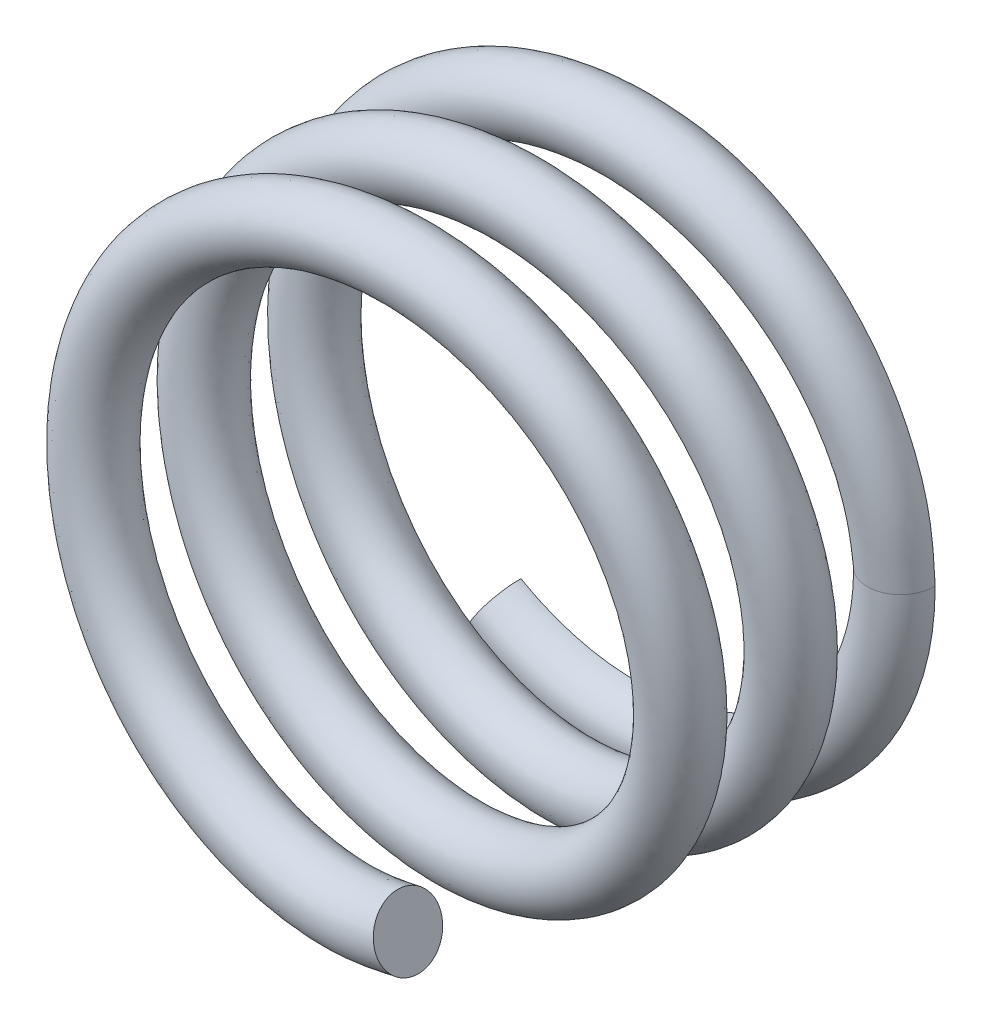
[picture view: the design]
ISO-10303-21;
HEADER;
FILE_DESCRIPTION(('STEP AP214'),'2;1');
FILE_NAME('part.step','',(''),(''),'','','');
FILE_SCHEMA(('AUTOMOTIVE_DESIGN { 1 0 10303 214 1 1 1 1 }'));
ENDSEC;
DATA;
#1=APPLICATION_CONTEXT('core data for automotive mechanical design processes');
#2=APPLICATION_PROTOCOL_DEFINITION('international standard','automotive_design',2000,#1);
#3=PRODUCT_CONTEXT('',#1,'mechanical');
#4=PRODUCT('Part','Part','',(#3));
#5=PRODUCT_RELATED_PRODUCT_CATEGORY('part','',(#4));
#6=PRODUCT_DEFINITION_FORMATION('','',#4);
#7=PRODUCT_DEFINITION_CONTEXT('part definition',#1,'design');
#8=PRODUCT_DEFINITION('design','',#6,#7);
#9=PRODUCT_DEFINITION_SHAPE('','',#8);
#10=(LENGTH_UNIT() NAMED_UNIT(*) SI_UNIT(.MILLI.,.METRE.));
#11=(NAMED_UNIT(*) PLANE_ANGLE_UNIT() SI_UNIT($,.RADIAN.));
#12=(NAMED_UNIT(*) SI_UNIT($,.STERADIAN.) SOLID_ANGLE_UNIT());
#13=UNCERTAINTY_MEASURE_WITH_UNIT(LENGTH_MEASURE(1.E-05),#10,'distance_accuracy_value','');
#14=(GEOMETRIC_REPRESENTATION_CONTEXT(3) GLOBAL_UNCERTAINTY_ASSIGNED_CONTEXT((#13)) GLOBAL_UNIT_ASSIGNED_CONTEXT((#10,
#11,#12)) REPRESENTATION_CONTEXT('',''));
#15=CARTESIAN_POINT('',(0.,0.,0.));
#16=DIRECTION('',(0.,0.,1.));
#17=DIRECTION('',(1.,0.,0.));
#18=AXIS2_PLACEMENT_3D('',#15,#16,#17);
#19=CARTESIAN_POINT('',(12.,0.,1.5));
#20=CARTESIAN_POINT('',(11.9603713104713,0.731177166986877,1.54849427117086));
#21=CARTESIAN_POINT('',(11.8809443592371,2.19666022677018,1.64569032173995));
#22=CARTESIAN_POINT('',(11.2620280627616,4.32325216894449,1.79155371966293));
#23=CARTESIAN_POINT('',(10.2896280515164,6.30509649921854,1.93755795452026));
#24=CARTESIAN_POINT('',(8.96763299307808,8.07535029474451,2.08335110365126));
#25=CARTESIAN_POINT('',(7.34519233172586,9.57242636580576,2.22917046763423));
#26=CARTESIAN_POINT('',(5.47846168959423,10.7517410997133,2.37496569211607));
#27=CARTESIAN_POINT('',(3.42708930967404,11.5698049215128,2.52086018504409));
#28=CARTESIAN_POINT('',(1.26135363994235,12.0005154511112,2.66665382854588));
#29=CARTESIAN_POINT('',(-0.946832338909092,12.0300652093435,2.81251271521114));
#30=CARTESIAN_POINT('',(-3.12287162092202,11.654859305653,2.95832053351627));
#31=CARTESIAN_POINT('',(-5.19533038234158,10.8922151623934,3.10417314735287));
#32=CARTESIAN_POINT('',(-7.09200037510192,9.76130690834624,3.25000059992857));
#33=CARTESIAN_POINT('',(-8.75386804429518,8.30714801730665,3.39582788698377));
#34=CARTESIAN_POINT('',(-10.119061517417,6.57134770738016,3.54167658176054));
#35=CARTESIAN_POINT('',(-11.1493056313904,4.61825453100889,3.68748521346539));
#36=CARTESIAN_POINT('',(-11.8021776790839,2.50856434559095,3.8333513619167));
#37=CARTESIAN_POINT('',(-12.0633531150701,0.315962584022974,3.97914646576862));
#38=CARTESIAN_POINT('',(-11.9177644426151,-1.88765780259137,4.12502086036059));
#39=CARTESIAN_POINT('',(-11.3747674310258,-4.02794086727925,4.27081308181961));
#40=CARTESIAN_POINT('',(-10.4502596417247,-6.03352237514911,4.41668500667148));
#41=CARTESIAN_POINT('',(-9.17529768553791,-7.83637417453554,4.56248507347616));
#42=CARTESIAN_POINT('',(-7.59434030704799,-9.37827116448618,4.70834416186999));
#43=CARTESIAN_POINT('',(-5.75731397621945,-10.6036082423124,4.85416105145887));
#44=CARTESIAN_POINT('',(-3.72922558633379,-11.4773479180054,5.00000024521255));
#45=CARTESIAN_POINT('',(-1.57485201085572,-11.9623402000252,5.14583849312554));
#46=CARTESIAN_POINT('',(0.631550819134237,-12.0515300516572,5.29165624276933));
#47=CARTESIAN_POINT('',(2.81672677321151,-11.7322774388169,5.43751456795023));
#48=CARTESIAN_POINT('',(4.90833399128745,-11.0244622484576,5.58331520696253));
#49=CARTESIAN_POINT('',(6.83434805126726,-9.94391600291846,5.72918674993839));
#50=CARTESIAN_POINT('',(8.53274353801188,-8.53284811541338,5.87497907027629));
#51=CARTESIAN_POINT('',(9.94446517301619,-6.83456494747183,6.02085362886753));
#52=CARTESIAN_POINT('',(11.02333168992,-4.90797393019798,6.16664846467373));
#53=CARTESIAN_POINT('',(11.7338559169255,-2.81700710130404,6.31251511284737));
#54=CARTESIAN_POINT('',(12.0494652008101,-0.631524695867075,6.45832269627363));
#55=CARTESIAN_POINT('',(11.9645671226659,1.57517466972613,6.60417242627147));
#56=CARTESIAN_POINT('',(11.4751000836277,3.72848434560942,6.74999977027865));
#57=CARTESIAN_POINT('',(10.6056574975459,5.75837192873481,6.89582804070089));
#58=CARTESIAN_POINT('',(9.37668509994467,7.59314053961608,7.04167687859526));
#59=CARTESIAN_POINT('',(7.83754685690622,9.17650104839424,7.18748520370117));
#60=CARTESIAN_POINT('',(6.03286015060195,10.4493495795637,7.33335126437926));
#61=CARTESIAN_POINT('',(4.02827918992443,11.3752927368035,7.47914645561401));
#62=CARTESIAN_POINT('',(1.88752245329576,11.9177855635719,7.62502088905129));
#63=CARTESIAN_POINT('',(-0.31580290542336,12.0627488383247,7.77081308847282));
#64=CARTESIAN_POINT('',(-2.50891296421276,11.8032485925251,7.91668499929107));
#65=CARTESIAN_POINT('',(-4.61751183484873,11.1477994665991,8.06248507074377));
#66=CARTESIAN_POINT('',(-6.5724856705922,10.120691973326,8.20834416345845));
#67=CARTESIAN_POINT('',(-8.30552284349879,8.75222611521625,8.35416105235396));
#68=CARTESIAN_POINT('',(-9.76321245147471,7.09339985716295,8.50000024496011));
#69=CARTESIAN_POINT('',(-10.8902055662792,5.19433968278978,8.64583849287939));
#70=CARTESIAN_POINT('',(-11.6568461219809,3.12348707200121,8.79165624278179));
#71=CARTESIAN_POINT('',(-12.0284753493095,0.946606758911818,8.93751456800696));
#72=CARTESIAN_POINT('',(-12.0016452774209,-1.26135683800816,9.08331520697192));
#73=CARTESIAN_POINT('',(-11.5691558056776,-3.42701221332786,9.22918674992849));
#74=CARTESIAN_POINT('',(-10.7519835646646,-5.47832626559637,9.37497907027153));
#75=CARTESIAN_POINT('',(-9.57306626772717,-7.34575168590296,9.52085362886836));
#76=CARTESIAN_POINT('',(-8.0741574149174,-8.96716408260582,9.66664846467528));
#77=CARTESIAN_POINT('',(-6.30509384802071,-10.2890570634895,9.8125151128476));
#78=CARTESIAN_POINT('',(-4.32410519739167,-11.2645705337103,9.95832269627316));
#79=CARTESIAN_POINT('',(-2.19917443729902,-11.8657352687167,10.1041724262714));
#80=CARTESIAN_POINT('',(-1.60519495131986E-06,-12.065633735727,10.2499997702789));
#81=CARTESIAN_POINT('',(2.19920874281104,-11.8660144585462,10.3958280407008));
#82=CARTESIAN_POINT('',(4.32395074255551,-11.2641669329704,10.5416768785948));
#83=CARTESIAN_POINT('',(6.30543594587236,-10.2896447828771,10.6874852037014));
#84=CARTESIAN_POINT('',(8.07366569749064,-8.96661755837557,10.8333512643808));
#85=CARTESIAN_POINT('',(9.57373955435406,-7.34627994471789,10.9791464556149));
#86=CARTESIAN_POINT('',(10.7512111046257,-5.47793880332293,11.1250208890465));
#87=CARTESIAN_POINT('',(11.5699443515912,-3.427247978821,11.2708130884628));
#88=CARTESIAN_POINT('',(12.000853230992,-1.26128638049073,11.4166849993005));
#89=CARTESIAN_POINT('',(12.0290769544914,0.946655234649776,11.5624850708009));
#90=CARTESIAN_POINT('',(11.6563598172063,3.1233395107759,11.7083441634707));
#91=CARTESIAN_POINT('',(10.8904093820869,5.19443501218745,11.8541610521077));
#92=CARTESIAN_POINT('',(9.76322272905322,7.09338571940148,12.0000002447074));
#93=CARTESIAN_POINT('',(8.30536920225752,8.75206173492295,12.1458384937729));
#94=CARTESIAN_POINT('',(6.57277627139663,10.1211088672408,12.2916562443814));
#95=CARTESIAN_POINT('',(4.61727980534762,11.1472422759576,12.4375145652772));
#96=CARTESIAN_POINT('',(2.50909074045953,11.8040237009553,12.5833151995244));
#97=CARTESIAN_POINT('',(0.315783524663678,12.0619260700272,12.7291867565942));
#98=CARTESIAN_POINT('',(-1.88765223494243,11.9186397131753,12.8749790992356));
#99=CARTESIAN_POINT('',(-4.02798501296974,11.3744889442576,13.0208536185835));
#100=CARTESIAN_POINT('',(-6.03322846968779,10.4499868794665,13.1666483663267));
#101=CARTESIAN_POINT('',(-7.8370936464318,9.1759951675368,13.3125151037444));
#102=CARTESIAN_POINT('',(-9.37701853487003,7.5934104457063,13.458322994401));
#103=CARTESIAN_POINT('',(-10.6053987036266,5.75824916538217,13.6041725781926));
#104=CARTESIAN_POINT('',(-11.4751097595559,3.72848984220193,13.7499989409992));
#105=CARTESIAN_POINT('',(-11.9648654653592,1.57523319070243,13.8958273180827));
#106=CARTESIAN_POINT('',(-12.048998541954,-0.631500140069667,14.041679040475));
#107=CARTESIAN_POINT('',(-11.7344478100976,-2.81713283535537,14.1874876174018));
#108=CARTESIAN_POINT('',(-11.0227502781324,-4.90769840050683,14.3333458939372));
#109=CARTESIAN_POINT('',(-9.94535705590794,-6.83518686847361,14.4791398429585));
#110=CARTESIAN_POINT('',(-8.53194028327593,-8.53214432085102,14.6250343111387));
#111=CARTESIAN_POINT('',(-6.83442993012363,-9.94417796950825,14.7708294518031));
#112=CARTESIAN_POINT('',(-4.90864738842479,-11.0234482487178,14.9166489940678));
#113=CARTESIAN_POINT('',(-2.81706134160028,-11.7353683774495,15.0624416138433));
#114=CARTESIAN_POINT('',(-0.631513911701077,-12.046249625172,15.2084468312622));
#115=CARTESIAN_POINT('',(1.58226116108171,-11.9782283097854,15.3543091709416));
#116=CARTESIAN_POINT('',(3.00051631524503,-11.600770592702,15.4515056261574));
#117=CARTESIAN_POINT('',(3.70812820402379,-11.4124451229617,15.4999999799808));
#118=CARTESIAN_POINT('',(15.,0.,1.5));
#119=CARTESIAN_POINT('',(14.9503984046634,0.915065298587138,1.54856790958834));
#120=CARTESIAN_POINT('',(14.8509829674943,2.74911148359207,1.64591155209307));
#121=CARTESIAN_POINT('',(14.0797344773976,5.39818093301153,1.79125837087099));
#122=CARTESIAN_POINT('',(12.8607492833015,7.88413226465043,1.93881104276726));
#123=CARTESIAN_POINT('',(11.2110255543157,10.0923728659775,2.08281692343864));
#124=CARTESIAN_POINT('',(9.17823055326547,11.9683646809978,2.22996355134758));
#125=CARTESIAN_POINT('',(6.85263971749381,13.4374504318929,2.37428555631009));
#126=CARTESIAN_POINT('',(4.27985179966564,14.4637051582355,2.52213780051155));
#127=CARTESIAN_POINT('',(1.58026878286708,15.0003668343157,2.66618767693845));
#128=CARTESIAN_POINT('',(-1.18706321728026,15.0374503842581,2.81337027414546));
#129=CARTESIAN_POINT('',(-3.90143343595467,14.5693225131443,2.95810576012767));
#130=CARTESIAN_POINT('',(-6.49546636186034,13.6147491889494,3.10473477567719));
#131=CARTESIAN_POINT('',(-8.8651140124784,12.2018001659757,3.25025394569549));
#132=CARTESIAN_POINT('',(-10.9413524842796,10.3849920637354,3.39577947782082));
#133=CARTESIAN_POINT('',(-12.6502472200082,8.21249416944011,3.54235768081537));
#134=CARTESIAN_POINT('',(-13.9352839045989,5.77604070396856,3.68704217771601));
#135=CARTESIAN_POINT('',(-14.7537885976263,3.13210446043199,3.83434581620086));
#136=CARTESIAN_POINT('',(-15.0790925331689,0.399344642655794,3.97852178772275));
#137=CARTESIAN_POINT('',(-14.8967742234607,-2.36396364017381,4.12614386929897));
#138=CARTESIAN_POINT('',(-14.2199435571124,-5.03096821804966,4.27022116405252));
#139=CARTESIAN_POINT('',(-13.0609662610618,-7.54551020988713,4.41773758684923));
#140=CARTESIAN_POINT('',(-11.4712442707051,-9.79319756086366,4.56211613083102));
#141=CARTESIAN_POINT('',(-9.49099316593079,-11.7245607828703,4.70910406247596));
#142=CARTESIAN_POINT('',(-7.19775492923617,-13.2541115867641,4.85417719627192));
#143=CARTESIAN_POINT('',(-4.66155947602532,-14.3467267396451,5.00024532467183));
#144=CARTESIAN_POINT('',(-1.96747160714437,-14.9533078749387,5.14631247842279));
#145=CARTESIAN_POINT('',(0.786829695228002,-15.064544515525,5.29138642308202));
#146=CARTESIAN_POINT('',(3.5239615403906,-14.6649121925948,5.43837365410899));
#147=CARTESIAN_POINT('',(6.13168689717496,-13.7822340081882,5.58275293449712));
#148=CARTESIAN_POINT('',(8.54655182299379,-12.4277533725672,5.73026881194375));
#149=CARTESIAN_POINT('',(10.6628244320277,-10.6692289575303,5.87434564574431));
#150=CARTESIAN_POINT('',(12.4332419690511,-8.53974111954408,6.02196817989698));
#151=CARTESIAN_POINT('',(13.7777293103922,-6.13846325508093,6.16614569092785));
#152=CARTESIAN_POINT('',(14.668281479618,-3.51792692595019,6.31345000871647));
#153=CARTESIAN_POINT('',(15.0618775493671,-0.791639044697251,6.45812812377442));
#154=CARTESIAN_POINT('',(14.9556091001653,1.97039074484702,6.6047017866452));
#155=CARTESIAN_POINT('',(14.3440717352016,4.66065168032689,6.75024483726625));
#156=CARTESIAN_POINT('',(13.2577782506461,7.19669863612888,6.89578881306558));
#157=CARTESIAN_POINT('',(11.7196865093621,9.49330067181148,7.04236158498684));
#158=CARTESIAN_POINT('',(9.79958063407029,11.4683488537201,7.18704044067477));
#159=CARTESIAN_POINT('',(7.53798021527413,13.0638137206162,7.33434417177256));
#160=CARTESIAN_POINT('',(5.03949497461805,14.217664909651,7.47852203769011));
#161=CARTESIAN_POINT('',(2.35509325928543,14.8981788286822,7.62614444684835));
#162=CARTESIAN_POINT('',(-0.390530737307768,15.0786246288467,7.77022116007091));
#163=CARTESIAN_POINT('',(-3.14014609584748,14.7534080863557,7.91773740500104));
#164=CARTESIAN_POINT('',(-5.76907499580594,13.9360660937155,8.06211611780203));
#165=CARTESIAN_POINT('',(-8.21784175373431,12.6495593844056,8.20910411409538));
#166=CARTESIAN_POINT('',(-10.3811805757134,10.9412174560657,8.35417720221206));
#167=CARTESIAN_POINT('',(-12.2040468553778,8.86678890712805,8.50024531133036));
#168=CARTESIAN_POINT('',(-13.6134587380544,6.49200294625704,8.64631247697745));
#169=CARTESIAN_POINT('',(-14.5703769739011,3.90688075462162,8.79138642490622));
#170=CARTESIAN_POINT('',(-15.0361243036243,1.18022050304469,8.93837365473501));
#171=CARTESIAN_POINT('',(-15.0024789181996,-1.5726362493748,9.08275293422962));
#172=CARTESIAN_POINT('',(-14.4605255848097,-4.28786680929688,9.23026881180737));
#173=CARTESIAN_POINT('',(-13.442033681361,-6.84397559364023,9.37434564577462));
#174=CARTESIAN_POINT('',(-11.9638595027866,-9.18579065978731,9.52196817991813));
#175=CARTESIAN_POINT('',(-10.0955779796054,-11.2065097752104,9.66614569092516));
#176=CARTESIAN_POINT('',(-7.87849558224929,-12.8632654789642,9.81345000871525));
#177=CARTESIAN_POINT('',(-5.40726960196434,-14.0800668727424,9.95812812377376));
#178=CARTESIAN_POINT('',(-2.74758441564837,-14.8325137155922,10.1047017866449));
#179=CARTESIAN_POINT('',(-1.87839495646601E-05,-15.0822434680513,10.2502448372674));
#180=CARTESIAN_POINT('',(2.74758834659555,-14.8327985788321,10.3957888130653));
#181=CARTESIAN_POINT('',(5.40708316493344,-14.0796754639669,10.5423615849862));
#182=CARTESIAN_POINT('',(7.87881095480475,-12.8638697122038,10.6870404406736));
#183=CARTESIAN_POINT('',(10.0950611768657,-11.2059856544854,10.8343441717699));
#184=CARTESIAN_POINT('',(11.9645132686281,-9.18634461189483,10.9785220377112));
#185=CARTESIAN_POINT('',(13.441246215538,-6.84361723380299,11.1261444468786));
#186=CARTESIAN_POINT('',(14.461304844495,-4.28813445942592,11.2702211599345));
#187=CARTESIAN_POINT('',(15.0016834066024,-1.57259741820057,11.4177374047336));
#188=CARTESIAN_POINT('',(15.0367286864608,1.18023510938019,11.5621161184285));
#189=CARTESIAN_POINT('',(14.5698986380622,3.90670313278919,11.7091041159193));
#190=CARTESIAN_POINT('',(13.6136773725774,6.49206730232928,11.8541772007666));
#191=CARTESIAN_POINT('',(12.204075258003,8.86674982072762,12.0002452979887));
#192=CARTESIAN_POINT('',(10.3810518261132,10.9410293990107,12.1463124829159));
#193=CARTESIAN_POINT('',(8.2181584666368,12.6499594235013,12.2913864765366));
#194=CARTESIAN_POINT('',(5.7688742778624,13.9354958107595,12.4383736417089));
#195=CARTESIAN_POINT('',(3.14035505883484,14.7541767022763,12.5827527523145));
#196=CARTESIAN_POINT('',(0.390544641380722,15.0778008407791,12.7302688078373));
#197=CARTESIAN_POINT('',(-2.35519079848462,14.8990382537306,12.8743462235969));
#198=CARTESIAN_POINT('',(-5.03917032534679,14.2168717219,13.0219684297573));
#199=CARTESIAN_POINT('',(-7.53831923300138,13.0644681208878,13.1661440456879));
#200=CARTESIAN_POINT('',(-9.79910440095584,11.4678626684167,13.3134482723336));
#201=CARTESIAN_POINT('',(-11.7199994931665,9.49359560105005,13.4581320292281));
#202=CARTESIAN_POINT('',(-13.2575009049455,7.19660851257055,13.6047111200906));
#203=CARTESIAN_POINT('',(-14.3440684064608,4.66069990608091,13.7502357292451));
#204=CARTESIAN_POINT('',(-14.9559093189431,1.97045734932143,13.8957558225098));
#205=CARTESIAN_POINT('',(-15.0614083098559,-0.791628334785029,14.0423839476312));
#206=CARTESIAN_POINT('',(-14.6688839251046,-3.51796234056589,14.187120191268));
#207=CARTESIAN_POINT('',(-13.777241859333,-6.13797895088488,14.3343021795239));
#208=CARTESIAN_POINT('',(-12.4341201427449,-8.54044994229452,14.4783523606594));
#209=CARTESIAN_POINT('',(-10.6615801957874,-10.6689719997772,14.6262045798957));
#210=CARTESIAN_POINT('',(-8.54668992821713,-12.4278679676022,14.7705265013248));
#211=CARTESIAN_POINT('',(-6.13373283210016,-13.7803223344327,14.9176733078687));
#212=CARTESIAN_POINT('',(-3.52432662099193,-14.6685911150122,15.0616786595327));
#213=CARTESIAN_POINT('',(-0.783143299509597,-15.0582172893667,15.2092323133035));
#214=CARTESIAN_POINT('',(1.97460691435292,-14.9736241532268,15.3545780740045));
#215=CARTESIAN_POINT('',(3.74956574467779,-14.5012879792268,15.4519221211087));
#216=CARTESIAN_POINT('',(4.63514826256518,-14.2656246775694,15.5004901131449));
#217=CARTESIAN_POINT('',(15.,0.,-1.5));
#218=CARTESIAN_POINT('',(14.9504707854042,0.915076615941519,-1.45143208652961));
#219=CARTESIAN_POINT('',(14.8512004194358,2.74914548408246,-1.35408843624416));
#220=CARTESIAN_POINT('',(14.0794493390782,5.39812567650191,-1.208741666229));
#221=CARTESIAN_POINT('',(12.8618126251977,7.88477268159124,-1.06118881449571));
#222=CARTESIAN_POINT('',(11.2106417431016,10.0920226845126,-0.917183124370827));
#223=CARTESIAN_POINT('',(9.17870901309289,11.968982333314,-0.770036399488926));
#224=CARTESIAN_POINT('',(6.8523267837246,13.436864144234,-0.625714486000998));
#225=CARTESIAN_POINT('',(4.28019566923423,14.4649222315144,-0.47786206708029));
#226=CARTESIAN_POINT('',(1.58022660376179,14.9999169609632,-0.333812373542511));
#227=CARTESIAN_POINT('',(-1.18714699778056,15.0382952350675,-0.186629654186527));
#228=CARTESIAN_POINT('',(-3.90137248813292,14.569125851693,-0.0418942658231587));
#229=CARTESIAN_POINT('',(-6.49573117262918,13.6152427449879,0.104734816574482));
#230=CARTESIAN_POINT('',(-8.86526154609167,12.2020077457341,0.250253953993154));
#231=CARTESIAN_POINT('',(-10.9413369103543,10.3849453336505,0.395779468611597));
#232=CARTESIAN_POINT('',(-12.6508095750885,8.21286733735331,0.542357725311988));
#233=CARTESIAN_POINT('',(-13.9348930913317,5.77585663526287,0.687042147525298));
#234=CARTESIAN_POINT('',(-14.7547492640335,3.13231244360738,0.83434589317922));
#235=CARTESIAN_POINT('',(-15.0784837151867,0.39931820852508,0.978521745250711));
#236=CARTESIAN_POINT('',(-14.8978694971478,-2.36414274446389,1.12614396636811));
#237=CARTESIAN_POINT('',(-14.2194003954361,-5.0307755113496,1.27022111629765));
#238=CARTESIAN_POINT('',(-13.0618599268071,-7.54604528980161,1.41773768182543));
#239=CARTESIAN_POINT('',(-11.4709771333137,-9.79296075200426,1.5621160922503));
#240=CARTESIAN_POINT('',(-9.49144976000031,-11.7251615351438,1.7091041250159));
#241=CARTESIAN_POINT('',(-7.1977695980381,-13.2541280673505,1.85417718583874));
#242=CARTESIAN_POINT('',(-4.66161192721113,-14.3469688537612,2.00024533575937));
#243=CARTESIAN_POINT('',(-1.96753792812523,-14.9537745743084,2.14631250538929));
#244=CARTESIAN_POINT('',(0.786838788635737,-15.0642823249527,2.29138640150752));
#245=CARTESIAN_POINT('',(3.52415401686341,-14.6657399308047,2.43837371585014));
#246=CARTESIAN_POINT('',(6.13147835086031,-13.7817265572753,2.5827528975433));
#247=CARTESIAN_POINT('',(8.5471577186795,-12.4286343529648,2.73026890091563));
#248=CARTESIAN_POINT('',(10.6623912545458,-10.6687889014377,2.87434559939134));
#249=CARTESIAN_POINT('',(12.4341564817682,-8.54035598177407,3.02196827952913));
#250=CARTESIAN_POINT('',(13.7772812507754,-6.13826856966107,3.16614564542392));
#251=CARTESIAN_POINT('',(14.6691868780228,-3.51812292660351,3.31345009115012));
#252=CARTESIAN_POINT('',(15.0616918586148,-0.79163612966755,3.4581280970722));
#253=CARTESIAN_POINT('',(14.9561285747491,1.97048377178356,3.60470182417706));
#254=CARTESIAN_POINT('',(14.3443071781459,4.66072450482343,3.75024484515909));
#255=CARTESIAN_POINT('',(13.2577366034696,7.19670354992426,3.89578880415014));
#256=CARTESIAN_POINT('',(11.7202178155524,9.49372262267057,4.04236163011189));
#257=CARTESIAN_POINT('',(9.79928390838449,11.4680325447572,4.18704041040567));
#258=CARTESIAN_POINT('',(7.53847417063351,13.0646617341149,4.33434424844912));
#259=CARTESIAN_POINT('',(5.03928173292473,14.2170943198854,4.47852199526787));
#260=CARTESIAN_POINT('',(2.3552614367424,14.8992763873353,4.62614454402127));
#261=CARTESIAN_POINT('',(-0.39051530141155,15.0780484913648,4.7702211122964));
#262=CARTESIAN_POINT('',(-3.14037878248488,14.7544231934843,4.91773749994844));
#263=CARTESIAN_POINT('',(-5.76893232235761,13.9357388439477,5.06211607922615));
#264=CARTESIAN_POINT('',(-8.21827203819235,12.6501793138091,5.20910417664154));
#265=CARTESIAN_POINT('',(-10.381191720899,10.9412365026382,5.35417719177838));
#266=CARTESIAN_POINT('',(-12.2042608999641,8.86691360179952,5.50024532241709));
#267=CARTESIAN_POINT('',(-13.6138821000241,6.49221023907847,5.64631250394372));
#268=CARTESIAN_POINT('',(-14.5701304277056,3.90679108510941,5.79138640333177));
#269=CARTESIAN_POINT('',(-15.0369710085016,1.18029323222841,5.93837371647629));
#270=CARTESIAN_POINT('',(-15.0019318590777,-1.57259472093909,6.08275289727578));
#271=CARTESIAN_POINT('',(-14.4615506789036,-4.28817081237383,6.23026890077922));
#272=CARTESIAN_POINT('',(-13.4414813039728,-6.84369960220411,6.37434559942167));
#273=CARTESIAN_POINT('',(-11.9647268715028,-9.18647041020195,6.52196827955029));
#274=CARTESIAN_POINT('',(-10.0952543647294,-11.2061438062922,6.66614564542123));
#275=CARTESIAN_POINT('',(-7.87896177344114,-12.8640659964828,6.8134500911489));
#276=CARTESIAN_POINT('',(-5.40720944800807,-14.079891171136,6.95812809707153));
#277=CARTESIAN_POINT('',(-2.74765646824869,-14.8330365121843,7.10470182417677));
#278=CARTESIAN_POINT('',(-2.22796085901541E-05,-15.0824898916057,7.25024484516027));
#279=CARTESIAN_POINT('',(2.74760588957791,-14.8327604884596,7.39578880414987));
#280=CARTESIAN_POINT('',(5.40732028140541,-14.0803111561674,7.54236163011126));
#281=CARTESIAN_POINT('',(7.87860182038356,-12.8634897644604,7.68704041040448));
#282=CARTESIAN_POINT('',(10.0957150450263,-11.2067174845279,7.83434424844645));
#283=CARTESIAN_POINT('',(11.9640365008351,-9.18596548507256,7.97852199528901));
#284=CARTESIAN_POINT('',(13.4422380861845,-6.8441163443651,8.12614454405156));
#285=CARTESIAN_POINT('',(14.4607521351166,-4.28797110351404,8.27022111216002));
#286=CARTESIAN_POINT('',(15.002720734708,-1.57268980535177,8.41773749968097));
#287=CARTESIAN_POINT('',(15.0363733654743,1.18020054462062,8.56211607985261));
#288=CARTESIAN_POINT('',(14.5706211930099,3.90692078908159,8.70910417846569));
#289=CARTESIAN_POINT('',(13.6136989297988,6.49207201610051,8.85417719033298));
#290=CARTESIAN_POINT('',(12.2042599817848,8.86691484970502,9.00024530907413));
#291=CARTESIAN_POINT('',(10.3813798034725,10.9413679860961,9.14631250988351));
#292=CARTESIAN_POINT('',(8.21799702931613,12.6497526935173,9.29138645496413));
#293=CARTESIAN_POINT('',(5.76920508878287,13.9362785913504,9.43837370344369));
#294=CARTESIAN_POINT('',(3.14022545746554,14.7536434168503,9.58275271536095));
#295=CARTESIAN_POINT('',(0.390572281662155,15.0788696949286,9.73026889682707));
#296=CARTESIAN_POINT('',(-2.35509906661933,14.8984281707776,9.87434617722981));
#297=CARTESIAN_POINT('',(-5.03954880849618,14.2179069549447,10.0219685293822));
#298=CARTESIAN_POINT('',(-7.53807046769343,13.0640458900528,10.166144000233));
#299=CARTESIAN_POINT('',(-9.79972077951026,11.4685519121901,10.3134483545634));
#300=CARTESIAN_POINT('',(-11.7198536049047,9.49348653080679,10.4581320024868));
#301=CARTESIAN_POINT('',(-13.2579834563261,7.19684387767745,10.6047111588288));
#302=CARTESIAN_POINT('',(-14.3442941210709,4.66077603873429,10.7502357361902));
#303=CARTESIAN_POINT('',(-14.9558467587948,1.97042258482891,10.895755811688));
#304=CARTESIAN_POINT('',(-15.0621063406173,-0.791657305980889,11.0423839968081));
#305=CARTESIAN_POINT('',(-14.6685339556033,-3.51789544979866,11.1871201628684));
#306=CARTESIAN_POINT('',(-13.7781067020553,-6.13835908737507,11.3343022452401));
#307=CARTESIAN_POINT('',(-12.4334755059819,-8.54002541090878,11.478352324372));
#308=CARTESIAN_POINT('',(-10.662389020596,-10.6697999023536,11.626204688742));
#309=CARTESIAN_POINT('',(-8.5465301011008,-12.4276278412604,11.7705264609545));
#310=CARTESIAN_POINT('',(-6.1341474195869,-13.78124598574,11.9176733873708));
#311=CARTESIAN_POINT('',(-3.5241616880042,-14.6678611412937,12.0616786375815));
#312=CARTESIAN_POINT('',(-0.783132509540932,-15.0589976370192,12.2092323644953));
#313=CARTESIAN_POINT('',(1.97463615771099,-14.9738962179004,12.3545780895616));
#314=CARTESIAN_POINT('',(3.74967652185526,-14.5016895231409,12.4519221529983));
#315=CARTESIAN_POINT('',(4.63529971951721,-14.2660908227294,12.5004901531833));
#316=CARTESIAN_POINT('',(12.,0.,-1.5));
#317=CARTESIAN_POINT('',(11.9604436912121,0.731188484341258,-1.45150572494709));
#318=CARTESIAN_POINT('',(11.8811618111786,2.19669422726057,-1.35430966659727));
#319=CARTESIAN_POINT('',(11.2617429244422,4.32319691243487,-1.20844631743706));
#320=CARTESIAN_POINT('',(10.2906913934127,6.30573691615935,-1.06244190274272));
#321=CARTESIAN_POINT('',(8.96724918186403,8.07500011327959,-0.916648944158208));
#322=CARTESIAN_POINT('',(7.34567079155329,9.573044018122,-0.770829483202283));
#323=CARTESIAN_POINT('',(5.47814875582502,10.7511548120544,-0.625034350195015));
#324=CARTESIAN_POINT('',(3.42743317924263,11.5710219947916,-0.479139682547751));
#325=CARTESIAN_POINT('',(1.26131146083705,12.0000655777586,-0.333346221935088));
#326=CARTESIAN_POINT('',(-0.946916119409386,12.0309100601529,-0.187487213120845));
#327=CARTESIAN_POINT('',(-3.12281067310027,11.6546626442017,-0.0416794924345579));
#328=CARTESIAN_POINT('',(-5.19559519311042,10.8927087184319,0.104173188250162));
#329=CARTESIAN_POINT('',(-7.09214790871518,9.7615144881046,0.250000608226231));
#330=CARTESIAN_POINT('',(-8.75385247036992,8.30710128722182,0.395827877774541));
#331=CARTESIAN_POINT('',(-10.1196238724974,6.57172087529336,0.541676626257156));
#332=CARTESIAN_POINT('',(-11.1489148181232,4.6180704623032,0.687485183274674));
#333=CARTESIAN_POINT('',(-11.803138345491,2.50877232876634,0.833351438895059));
#334=CARTESIAN_POINT('',(-12.0627442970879,0.315936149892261,0.979146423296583));
#335=CARTESIAN_POINT('',(-11.9188597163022,-1.88783690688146,1.12502095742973));
#336=CARTESIAN_POINT('',(-11.3742242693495,-4.02774816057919,1.27081303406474));
#337=CARTESIAN_POINT('',(-10.4511533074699,-6.03405745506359,1.41668510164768));
#338=CARTESIAN_POINT('',(-9.17503054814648,-7.83613736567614,1.56248503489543));
#339=CARTESIAN_POINT('',(-7.59479690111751,-9.37887191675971,1.70834422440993));
#340=CARTESIAN_POINT('',(-5.75732864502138,-10.6036247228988,1.85416104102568));
#341=CARTESIAN_POINT('',(-3.7292780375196,-11.4775900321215,2.0000002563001));
#342=CARTESIAN_POINT('',(-1.57491833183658,-11.9628068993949,2.14583852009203));
#343=CARTESIAN_POINT('',(0.631559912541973,-12.051267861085,2.29165622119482));
#344=CARTESIAN_POINT('',(2.81691924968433,-11.7331051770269,2.43751462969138));
#345=CARTESIAN_POINT('',(4.9081254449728,-11.0239547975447,2.5833151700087));
#346=CARTESIAN_POINT('',(6.83495394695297,-9.9447969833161,2.72918683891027));
#347=CARTESIAN_POINT('',(8.53231036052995,-8.53240805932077,2.87497902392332));
#348=CARTESIAN_POINT('',(9.94537968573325,-6.83517980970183,3.02085372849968));
#349=CARTESIAN_POINT('',(11.0228836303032,-4.90777924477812,3.16664841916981));
#350=CARTESIAN_POINT('',(11.7347613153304,-2.81720310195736,3.31251519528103));
#351=CARTESIAN_POINT('',(12.0492795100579,-0.631521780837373,3.45832266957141));
#352=CARTESIAN_POINT('',(11.9650865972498,1.57526769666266,3.60417246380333));
#353=CARTESIAN_POINT('',(11.475335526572,3.72855717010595,3.74999977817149));
#354=CARTESIAN_POINT('',(10.6056158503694,5.75837684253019,3.89582803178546));
#355=CARTESIAN_POINT('',(9.37721640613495,7.59356249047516,4.04167692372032));
#356=CARTESIAN_POINT('',(7.83725013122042,9.17618473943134,4.18748517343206));
#357=CARTESIAN_POINT('',(6.03335410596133,10.4501975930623,4.33335134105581));
#358=CARTESIAN_POINT('',(4.02806594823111,11.374722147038,4.47914641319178));
#359=CARTESIAN_POINT('',(1.88769063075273,11.918883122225,4.62502098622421));
#360=CARTESIAN_POINT('',(-0.315787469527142,12.0621727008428,4.77081304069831));
#361=CARTESIAN_POINT('',(-2.50914565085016,11.8042636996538,4.91668509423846));
#362=CARTESIAN_POINT('',(-4.61736916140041,11.1474722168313,5.0624850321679));
#363=CARTESIAN_POINT('',(-6.57291595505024,10.1213119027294,5.20834422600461));
#364=CARTESIAN_POINT('',(-8.30553398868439,8.75224516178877,5.35416104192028));
#365=CARTESIAN_POINT('',(-9.76342649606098,7.09352455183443,5.50000025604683));
#366=CARTESIAN_POINT('',(-10.8906289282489,5.19454697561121,5.64583851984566));
#367=CARTESIAN_POINT('',(-11.6565995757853,3.123397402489,5.79165622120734));
#368=CARTESIAN_POINT('',(-12.0293220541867,0.946679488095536,5.93751462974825));
#369=CARTESIAN_POINT('',(-12.001098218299,-1.26131530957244,6.08331517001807));
#370=CARTESIAN_POINT('',(-11.5701808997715,-3.42731621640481,6.22918683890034));
#371=CARTESIAN_POINT('',(-10.7514311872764,-5.47805027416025,6.37497902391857));
#372=CARTESIAN_POINT('',(-9.57393363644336,-7.3464314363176,6.52085372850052));
#373=CARTESIAN_POINT('',(-8.07383380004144,-8.9667981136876,6.66664841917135));
#374=CARTESIAN_POINT('',(-6.30556003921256,-10.2898575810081,6.81251519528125));
#375=CARTESIAN_POINT('',(-4.32404504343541,-11.2643948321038,6.95832266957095));
#376=CARTESIAN_POINT('',(-2.19924648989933,-11.8662580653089,7.10417246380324));
#377=CARTESIAN_POINT('',(-5.10085397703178E-06,-12.0658801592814,7.24999977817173));
#378=CARTESIAN_POINT('',(2.1992262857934,-11.8659763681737,7.39582803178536));
#379=CARTESIAN_POINT('',(4.32418785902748,-11.264802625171,7.54167692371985));
#380=CARTESIAN_POINT('',(6.30522681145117,-10.2892648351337,7.68748517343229));
#381=CARTESIAN_POINT('',(8.07431956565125,-8.96734938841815,7.83335134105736));
#382=CARTESIAN_POINT('',(9.57326278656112,-7.34590081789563,7.97914641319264));
#383=CARTESIAN_POINT('',(10.7522029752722,-5.47843791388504,8.12502098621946));
#384=CARTESIAN_POINT('',(11.5693916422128,-3.42708462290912,8.27081304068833));
#385=CARTESIAN_POINT('',(12.0018905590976,-1.26137876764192,8.41668509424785));
#386=CARTESIAN_POINT('',(12.0287216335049,0.94662066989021,8.56248503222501));
#387=CARTESIAN_POINT('',(11.657082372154,3.12355716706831,8.70834422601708));
#388=CARTESIAN_POINT('',(10.8904309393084,5.19443972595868,8.85416104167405));
#389=CARTESIAN_POINT('',(9.76340745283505,7.09355074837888,9.00000025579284));
#390=CARTESIAN_POINT('',(8.30569717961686,8.75240032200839,9.14583852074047));
#391=CARTESIAN_POINT('',(6.57261483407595,10.1209021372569,9.29165622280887));
#392=CARTESIAN_POINT('',(4.6176106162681,11.1480250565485,9.43751462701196));
#393=CARTESIAN_POINT('',(2.50896113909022,11.8034904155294,9.58331516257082));
#394=CARTESIAN_POINT('',(0.315811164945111,12.0629949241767,9.72918684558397));
#395=CARTESIAN_POINT('',(-1.88756050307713,11.9180296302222,9.87497905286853));
#396=CARTESIAN_POINT('',(-4.02836349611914,11.3755241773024,10.0208537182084));
#397=CARTESIAN_POINT('',(-6.03297970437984,10.4495646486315,10.1666483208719));
#398=CARTESIAN_POINT('',(-7.83771002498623,9.17668441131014,10.3125151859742));
#399=CARTESIAN_POINT('',(-9.3768726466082,7.59330137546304,10.4583229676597));
#400=CARTESIAN_POINT('',(-10.6058812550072,5.75848453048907,10.6041726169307));
#401=CARTESIAN_POINT('',(-11.475335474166,3.72856597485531,10.7499989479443));
#402=CARTESIAN_POINT('',(-11.9648029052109,1.57519842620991,10.8958273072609));
#403=CARTESIAN_POINT('',(-12.0496965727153,-0.631529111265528,11.0416790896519));
#404=CARTESIAN_POINT('',(-11.7340978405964,-2.81706594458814,11.1874875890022));
#405=CARTESIAN_POINT('',(-11.0236151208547,-4.90807853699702,11.3333459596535));
#406=CARTESIAN_POINT('',(-9.94471241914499,-6.83476233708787,11.4791398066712));
#407=CARTESIAN_POINT('',(-8.53274910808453,-8.53297222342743,11.625034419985));
#408=CARTESIAN_POINT('',(-6.8342701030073,-9.94393784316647,11.7708294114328));
#409=CARTESIAN_POINT('',(-4.90906197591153,-11.0243719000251,11.9166490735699));
#410=CARTESIAN_POINT('',(-2.81689640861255,-11.734638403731,12.0624415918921));
#411=CARTESIAN_POINT('',(-0.631503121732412,-12.0470299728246,12.208446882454));
#412=CARTESIAN_POINT('',(1.58229040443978,-11.9785003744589,12.3543091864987));
#413=CARTESIAN_POINT('',(3.0006270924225,-11.6011721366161,12.451505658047));
#414=CARTESIAN_POINT('',(3.70827966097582,-11.4129112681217,12.5000000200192));
#415=CARTESIAN_POINT('',(9.,0.,-1.5));
#416=CARTESIAN_POINT('',(8.97041659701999,0.547300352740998,-1.45157936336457));
#417=CARTESIAN_POINT('',(8.91112320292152,1.64424297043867,-1.35453089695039));
#418=CARTESIAN_POINT('',(8.44403650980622,3.24826814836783,-1.20815096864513));
#419=CARTESIAN_POINT('',(7.71957016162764,4.72670115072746,-1.06369499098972));
#420=CARTESIAN_POINT('',(6.72385662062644,6.05797754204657,-0.91611476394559));
#421=CARTESIAN_POINT('',(5.51263257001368,7.17710570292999,-0.771622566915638));
#422=CARTESIAN_POINT('',(4.10397072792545,8.06544547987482,-0.624354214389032));
#423=CARTESIAN_POINT('',(2.57467068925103,8.67712175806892,-0.48041729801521));
#424=CARTESIAN_POINT('',(0.942396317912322,9.00021419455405,-0.332880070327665));
#425=CARTESIAN_POINT('',(-0.706685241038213,9.02352488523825,-0.188344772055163));
#426=CARTESIAN_POINT('',(-2.34424885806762,8.74019943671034,-0.0414647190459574));
#427=CARTESIAN_POINT('',(-3.89545921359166,8.17017469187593,0.103611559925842));
#428=CARTESIAN_POINT('',(-5.3190342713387,7.32102123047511,0.24974726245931));
#429=CARTESIAN_POINT('',(-6.56636803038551,6.22925724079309,0.395876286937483));
#430=CARTESIAN_POINT('',(-7.58843816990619,4.93057441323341,0.540995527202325));
#431=CARTESIAN_POINT('',(-8.36293654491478,3.46028428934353,0.68792821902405));
#432=CARTESIAN_POINT('',(-8.85152742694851,1.8852322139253,0.8323569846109));
#433=CARTESIAN_POINT('',(-9.04700487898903,0.232554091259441,0.979771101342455));
#434=CARTESIAN_POINT('',(-8.93984993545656,-1.41153106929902,1.12389794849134));
#435=CARTESIAN_POINT('',(-8.52904814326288,-3.02472080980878,1.27140495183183));
#436=CARTESIAN_POINT('',(-7.8404466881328,-4.52206962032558,1.41563252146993));
#437=CARTESIAN_POINT('',(-6.87908396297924,-5.87931397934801,1.56285397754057));
#438=CARTESIAN_POINT('',(-5.69814404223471,-7.0325822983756,1.70758432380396));
#439=CARTESIAN_POINT('',(-4.31688769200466,-7.95312137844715,1.85414489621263));
#440=CARTESIAN_POINT('',(-2.79694414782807,-8.6082112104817,1.99975517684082));
#441=CARTESIAN_POINT('',(-1.18229873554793,-8.97183922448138,2.14536453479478));
#442=CARTESIAN_POINT('',(0.476281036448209,-9.03825339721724,2.29192604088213));
#443=CARTESIAN_POINT('',(2.10968448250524,-8.80047042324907,2.43665554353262));
#444=CARTESIAN_POINT('',(3.68477253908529,-8.26618303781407,2.58387744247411));
#445=CARTESIAN_POINT('',(5.12275017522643,-7.4609596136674,2.72810477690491));
#446=CARTESIAN_POINT('',(6.4022294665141,-6.39602721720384,2.8756124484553));
#447=CARTESIAN_POINT('',(7.45660288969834,-5.13000363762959,3.01973917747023));
#448=CARTESIAN_POINT('',(8.26848600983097,-3.67728991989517,3.16715119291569));
#449=CARTESIAN_POINT('',(8.80033575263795,-2.11628327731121,3.31158029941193));
#450=CARTESIAN_POINT('',(9.03686716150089,-0.471407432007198,3.45851724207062));
#451=CARTESIAN_POINT('',(8.9740446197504,1.18005162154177,3.6036431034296));
#452=CARTESIAN_POINT('',(8.60636387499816,2.79638983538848,3.74975471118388));
#453=CARTESIAN_POINT('',(7.95349509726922,4.32005013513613,3.89586725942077));
#454=CARTESIAN_POINT('',(7.03421499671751,5.69340235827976,4.04099221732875));
#455=CARTESIAN_POINT('',(5.87521635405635,6.88433693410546,4.18792993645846));
#456=CARTESIAN_POINT('',(4.52823404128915,7.83573345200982,4.33235843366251));
#457=CARTESIAN_POINT('',(3.01685016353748,8.53234997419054,4.47977083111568));
#458=CARTESIAN_POINT('',(1.42011982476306,8.9384898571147,4.62389742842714));
#459=CARTESIAN_POINT('',(-0.241059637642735,9.04629691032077,4.77140496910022));
#460=CARTESIAN_POINT('',(-1.87791251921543,8.85410420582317,4.91563268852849));
#461=CARTESIAN_POINT('',(-3.46580600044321,8.35920558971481,5.06285398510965));
#462=CARTESIAN_POINT('',(-4.92755987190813,7.59244449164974,5.20758427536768));
#463=CARTESIAN_POINT('',(-6.22987625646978,6.56325382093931,5.35414489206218));
#464=CARTESIAN_POINT('',(-7.32259209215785,5.32013550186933,5.49975518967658));
#465=CARTESIAN_POINT('',(-8.16737575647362,3.89688371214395,5.64536453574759));
#466=CARTESIAN_POINT('',(-8.74306872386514,2.3400037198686,5.79192603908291));
#467=CARTESIAN_POINT('',(-9.02167309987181,0.71306574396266,5.9366555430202));
#468=CARTESIAN_POINT('',(-9.00026457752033,-0.950035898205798,6.08387744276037));
#469=CARTESIAN_POINT('',(-8.67881112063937,-2.56646162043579,6.22810477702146));
#470=CARTESIAN_POINT('',(-8.06138107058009,-4.11240094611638,6.37561244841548));
#471=CARTESIAN_POINT('',(-7.18314040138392,-5.50639246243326,6.51973917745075));
#472=CARTESIAN_POINT('',(-6.05241323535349,-6.72745242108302,6.66715119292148));
#473=CARTESIAN_POINT('',(-4.73215830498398,-7.71564916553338,6.81158029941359));
#474=CARTESIAN_POINT('',(-3.24088063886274,-8.44889849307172,6.95851724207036));
#475=CARTESIAN_POINT('',(-1.65083651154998,-8.8994796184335,7.1036431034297));
#476=CARTESIAN_POINT('',(1.20779006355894E-05,-9.04927042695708,7.2497547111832));
#477=CARTESIAN_POINT('',(1.6508466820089,-8.89919224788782,7.39586725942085));
#478=CARTESIAN_POINT('',(3.24105543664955,-8.4492940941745,7.54099221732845));
#479=CARTESIAN_POINT('',(4.73185180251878,-7.71503990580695,7.68792993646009));
#480=CARTESIAN_POINT('',(6.05292408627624,-6.72798129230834,7.83235843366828));
#481=CARTESIAN_POINT('',(7.18248907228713,-5.5058361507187,7.97977083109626));
#482=CARTESIAN_POINT('',(8.06216786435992,-4.11275948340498,8.12389742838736));
#483=CARTESIAN_POINT('',(8.67803114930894,-2.56619814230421,8.27140496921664));
#484=CARTESIAN_POINT('',(9.00106038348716,-0.950067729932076,8.41563268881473));
#485=CARTESIAN_POINT('',(9.02106990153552,0.713040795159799,8.56285398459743));
#486=CARTESIAN_POINT('',(8.74354355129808,2.34019354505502,8.70758427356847));
#487=CARTESIAN_POINT('',(8.16716294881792,3.89680743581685,8.85414489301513));
#488=CARTESIAN_POINT('',(7.32255492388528,5.32018664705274,8.99975520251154));
#489=CARTESIAN_POINT('',(6.23001455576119,6.56343265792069,9.14536453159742));
#490=CARTESIAN_POINT('',(4.92723263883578,7.59205158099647,9.29192599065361));
#491=CARTESIAN_POINT('',(3.46601614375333,8.35977152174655,9.43665555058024));
#492=CARTESIAN_POINT('',(1.87769682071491,8.85333741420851,9.58387760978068));
#493=CARTESIAN_POINT('',(0.241050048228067,9.0471201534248,9.72810479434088));
#494=CARTESIAN_POINT('',(-1.42002193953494,8.93763108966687,9.87561192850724));
#495=CARTESIAN_POINT('',(-3.01717818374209,8.53314139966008,10.0197389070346));
#496=CARTESIAN_POINT('',(-4.52788894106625,7.83508340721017,10.1671526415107));
#497=CARTESIAN_POINT('',(-5.8756992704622,6.88481691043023,10.311582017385));
#498=CARTESIAN_POINT('',(-7.03389168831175,5.6931162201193,10.4585139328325));
#499=CARTESIAN_POINT('',(-7.95377905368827,4.32012518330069,10.6036340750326));
#500=CARTESIAN_POINT('',(-8.60637682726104,2.79635591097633,10.7497621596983));
#501=CARTESIAN_POINT('',(-8.97375905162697,1.17997426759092,10.8958988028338));
#502=CARTESIAN_POINT('',(-9.03728680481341,-0.471400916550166,11.0409741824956));
#503=CARTESIAN_POINT('',(-8.79966172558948,-2.11623643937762,11.1878550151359));
#504=CARTESIAN_POINT('',(-8.26912353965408,-3.67779798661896,11.3323896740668));
#505=CARTESIAN_POINT('',(-7.45594933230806,-5.12949926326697,11.4799272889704));
#506=CARTESIAN_POINT('',(-6.40310919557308,-6.39614454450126,11.6238641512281));
#507=CARTESIAN_POINT('',(-5.12201010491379,-7.46024784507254,11.7711323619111));
#508=CARTESIAN_POINT('',(-3.68397653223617,-8.26749781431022,11.9156247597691));
#509=CARTESIAN_POINT('',(-2.10963112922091,-8.80141566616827,12.0632045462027));
#510=CARTESIAN_POINT('',(-0.479873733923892,-9.03506230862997,12.2076614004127));
#511=CARTESIAN_POINT('',(1.18994465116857,-8.98310453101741,12.3540402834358));
#512=CARTESIAN_POINT('',(2.25157766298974,-8.70065475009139,12.4510891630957));
#513=CARTESIAN_POINT('',(2.78125960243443,-8.55973171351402,12.4995098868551));
#514=CARTESIAN_POINT('',(9.,0.,1.5));
#515=CARTESIAN_POINT('',(8.97034421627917,0.547289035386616,1.54842063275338));
#516=CARTESIAN_POINT('',(8.91090575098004,1.64420896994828,1.64546909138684));
#517=CARTESIAN_POINT('',(8.44432164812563,3.24832340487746,1.79184906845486));
#518=CARTESIAN_POINT('',(7.71850681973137,4.72606073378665,1.93630486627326));
#519=CARTESIAN_POINT('',(6.72424043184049,6.05832772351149,2.08388528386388));
#520=CARTESIAN_POINT('',(5.51215411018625,7.17648805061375,2.22837738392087));
#521=CARTESIAN_POINT('',(4.10428366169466,8.06603176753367,2.37564582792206));
#522=CARTESIAN_POINT('',(2.57432681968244,8.67590468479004,2.51958256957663));
#523=CARTESIAN_POINT('',(0.942438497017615,9.00066406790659,2.6671199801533));
#524=CARTESIAN_POINT('',(-0.706601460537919,9.02268003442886,2.81165515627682));
#525=CARTESIAN_POINT('',(-2.34430980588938,8.74039609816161,2.95853530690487));
#526=CARTESIAN_POINT('',(-3.89519440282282,8.16968113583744,3.10361151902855));
#527=CARTESIAN_POINT('',(-5.31888673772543,7.32081365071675,3.24974725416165));
#528=CARTESIAN_POINT('',(-6.56638360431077,6.22930397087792,3.39587629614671));
#529=CARTESIAN_POINT('',(-7.58787581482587,4.93020124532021,3.54099548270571));
#530=CARTESIAN_POINT('',(-8.36332735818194,3.46046835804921,3.68792824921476));
#531=CARTESIAN_POINT('',(-8.85056676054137,1.88502423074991,3.83235690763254));
#532=CARTESIAN_POINT('',(-9.0476136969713,0.232580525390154,3.97977114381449));
#533=CARTESIAN_POINT('',(-8.93875466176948,-1.41135196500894,4.1238978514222));
#534=CARTESIAN_POINT('',(-8.52959130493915,-3.02491351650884,4.2714049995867));
#535=CARTESIAN_POINT('',(-7.83955302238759,-4.5215345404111,4.41563242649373));
#536=CARTESIAN_POINT('',(-6.87935110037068,-5.87955078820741,4.5628540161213));
#537=CARTESIAN_POINT('',(-5.69768744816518,-7.03198154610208,4.70758426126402));
#538=CARTESIAN_POINT('',(-4.31687302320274,-7.95310489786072,4.85414490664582));
#539=CARTESIAN_POINT('',(-2.79689169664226,-8.60796909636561,4.99975516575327));
#540=CARTESIAN_POINT('',(-1.18223241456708,-8.9713725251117,5.14536450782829));
#541=CARTESIAN_POINT('',(0.476271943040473,-9.03851558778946,5.29192606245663));
#542=CARTESIAN_POINT('',(2.10949200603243,-8.79964268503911,5.43665548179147));
#543=CARTESIAN_POINT('',(3.68498108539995,-8.26669048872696,5.58387747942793));
#544=CARTESIAN_POINT('',(5.12214427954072,-7.46007863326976,5.72810468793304));
#545=CARTESIAN_POINT('',(6.40266264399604,-6.39646727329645,5.87561249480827));
#546=CARTESIAN_POINT('',(7.45568837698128,-5.1293887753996,6.01973907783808));
#547=CARTESIAN_POINT('',(8.26893406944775,-3.67748460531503,6.16715123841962));
#548=CARTESIAN_POINT('',(8.79943035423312,-2.11608727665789,6.31158021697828));
#549=CARTESIAN_POINT('',(9.03705285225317,-0.471410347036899,6.45851726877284));
#550=CARTESIAN_POINT('',(8.97352514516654,1.17995859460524,6.60364306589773));
#551=CARTESIAN_POINT('',(8.60612843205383,2.79631701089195,6.74975470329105));
#552=CARTESIAN_POINT('',(7.95353674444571,4.32004522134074,6.89586726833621));
#553=CARTESIAN_POINT('',(7.03368369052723,5.69298040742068,7.04099217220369));
#554=CARTESIAN_POINT('',(5.87551307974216,6.88465324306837,7.18792996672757));
#555=CARTESIAN_POINT('',(4.52774008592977,7.83488543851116,7.33235835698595));
#556=CARTESIAN_POINT('',(3.01706340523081,8.53292056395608,7.47977087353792));
#557=CARTESIAN_POINT('',(1.41995164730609,8.9373922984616,7.62389733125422));
#558=CARTESIAN_POINT('',(-0.241075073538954,9.04687304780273,7.77140501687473));
#559=CARTESIAN_POINT('',(-1.87767983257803,8.85308909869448,7.91563259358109));
#560=CARTESIAN_POINT('',(-3.46594867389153,8.3595328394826,8.06285402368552));
#561=CARTESIAN_POINT('',(-4.9271295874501,7.59182456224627,8.20758421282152));
#562=CARTESIAN_POINT('',(-6.22986511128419,6.56323477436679,8.35414490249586));
#563=CARTESIAN_POINT('',(-7.32237804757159,5.32001080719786,8.49975517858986));
#564=CARTESIAN_POINT('',(-8.16695239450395,3.89667641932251,8.64536450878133));
#565=CARTESIAN_POINT('',(-8.74331527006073,2.34009338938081,8.79192606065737));
#566=CARTESIAN_POINT('',(-9.02082639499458,0.712993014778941,8.93665548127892));
#567=CARTESIAN_POINT('',(-9.00081163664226,-0.95007742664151,9.08387747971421));
#568=CARTESIAN_POINT('',(-8.67778602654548,-2.56615761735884,9.22810468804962));
#569=CARTESIAN_POINT('',(-8.06193344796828,-4.1126769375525,9.37561249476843));
#570=CARTESIAN_POINT('',(-7.18227303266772,-5.50571271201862,9.51973907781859));
#571=CARTESIAN_POINT('',(-6.05273685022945,-6.72781839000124,9.66715123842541));
#572=CARTESIAN_POINT('',(-4.73169211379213,-7.71484864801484,9.81158021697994));
#573=CARTESIAN_POINT('',(-3.24094079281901,-8.44907419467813,9.95851726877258));
#574=CARTESIAN_POINT('',(-1.65076445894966,-8.89895682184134,10.1036430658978));
#575=CARTESIAN_POINT('',(1.55735596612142E-05,-9.0490240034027,10.2497547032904));
#576=CARTESIAN_POINT('',(1.65082913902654,-8.8992303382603,10.3958672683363));
#577=CARTESIAN_POINT('',(3.24081832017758,-8.44865840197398,10.5409921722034));
#578=CARTESIAN_POINT('',(4.73206093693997,-7.71541985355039,10.6879299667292));
#579=CARTESIAN_POINT('',(6.05227021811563,-6.72724946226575,10.8323583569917));
#580=CARTESIAN_POINT('',(7.18296584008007,-5.50621527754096,10.9797708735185));
#581=CARTESIAN_POINT('',(8.06117599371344,-4.11226037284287,11.1238973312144));
#582=CARTESIAN_POINT('',(8.67858385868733,-2.56636149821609,11.2714050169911));
#583=CARTESIAN_POINT('',(9.00002305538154,-0.949975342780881,11.4156325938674));
#584=CARTESIAN_POINT('',(9.02142522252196,0.713075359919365,11.5628540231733));
#585=CARTESIAN_POINT('',(8.7428209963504,2.33997588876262,11.7075842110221));
#586=CARTESIAN_POINT('',(8.16714139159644,3.89680272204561,11.8541449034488));
#587=CARTESIAN_POINT('',(7.32237020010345,5.32002161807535,11.9997551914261));
#588=CARTESIAN_POINT('',(6.22968657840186,6.56309407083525,12.1453645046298));
#589=CARTESIAN_POINT('',(4.92739407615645,7.59225831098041,12.2919260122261));
#590=CARTESIAN_POINT('',(3.46568533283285,8.35898874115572,12.4366554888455));
#591=CARTESIAN_POINT('',(1.87782642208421,8.85387069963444,12.5838776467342));
#592=CARTESIAN_POINT('',(0.241022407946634,9.04605129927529,12.7281047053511));
#593=CARTESIAN_POINT('',(-1.42011367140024,8.9382411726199,12.8756119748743));
#594=CARTESIAN_POINT('',(-3.01679970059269,8.53210616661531,13.0197388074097));
#595=CARTESIAN_POINT('',(-4.5281377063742,7.83550563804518,13.1671526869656));
#596=CARTESIAN_POINT('',(-5.87508289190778,6.8841276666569,13.3115819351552));
#597=CARTESIAN_POINT('',(-7.03403757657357,5.69322529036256,13.4585139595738));
#598=CARTESIAN_POINT('',(-7.95329650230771,4.31988981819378,13.6036340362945));
#599=CARTESIAN_POINT('',(-8.60615111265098,2.79627977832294,13.7497621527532));
#600=CARTESIAN_POINT('',(-8.97382161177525,1.18000903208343,13.8958988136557));
#601=CARTESIAN_POINT('',(-9.03658877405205,-0.471371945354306,14.0409741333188));
#602=CARTESIAN_POINT('',(-8.80001169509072,-2.11630333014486,14.1878550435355));
#603=CARTESIAN_POINT('',(-8.26825869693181,-3.67741785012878,14.3323896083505));
#604=CARTESIAN_POINT('',(-7.45659396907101,-5.1299237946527,14.4799273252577));
#605=CARTESIAN_POINT('',(-6.40230037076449,-6.39531664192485,14.6238640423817));
#606=CARTESIAN_POINT('',(-5.12216993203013,-7.46048797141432,14.7711324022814));
#607=CARTESIAN_POINT('',(-3.68356194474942,-8.26657416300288,14.915624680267));
#608=CARTESIAN_POINT('',(-2.10979606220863,-8.80214563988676,15.0632045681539));
#609=CARTESIAN_POINT('',(-0.479884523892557,-9.03428196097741,15.2076613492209));
#610=CARTESIAN_POINT('',(1.1899154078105,-8.98283246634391,15.3540402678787));
#611=CARTESIAN_POINT('',(2.25146688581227,-8.70025320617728,15.4510891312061));
#612=CARTESIAN_POINT('',(2.7811081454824,-8.55926556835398,15.4995098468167));
#613=CARTESIAN_POINT('',(12.,0.,1.5));
#614=CARTESIAN_POINT('',(11.9603713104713,0.731177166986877,1.54849427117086));
#615=CARTESIAN_POINT('',(11.8809443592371,2.19666022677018,1.64569032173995));
#616=CARTESIAN_POINT('',(11.2620280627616,4.32325216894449,1.79155371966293));
#617=CARTESIAN_POINT('',(10.2896280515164,6.30509649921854,1.93755795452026));
#618=CARTESIAN_POINT('',(8.96763299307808,8.07535029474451,2.08335110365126));
#619=CARTESIAN_POINT('',(7.34519233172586,9.57242636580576,2.22917046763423));
#620=CARTESIAN_POINT('',(5.47846168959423,10.7517410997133,2.37496569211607));
#621=CARTESIAN_POINT('',(3.42708930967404,11.5698049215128,2.52086018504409));
#622=CARTESIAN_POINT('',(1.26135363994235,12.0005154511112,2.66665382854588));
#623=CARTESIAN_POINT('',(-0.946832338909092,12.0300652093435,2.81251271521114));
#624=CARTESIAN_POINT('',(-3.12287162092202,11.654859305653,2.95832053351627));
#625=CARTESIAN_POINT('',(-5.19533038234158,10.8922151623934,3.10417314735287));
#626=CARTESIAN_POINT('',(-7.09200037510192,9.76130690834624,3.25000059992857));
#627=CARTESIAN_POINT('',(-8.75386804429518,8.30714801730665,3.39582788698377));
#628=CARTESIAN_POINT('',(-10.119061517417,6.57134770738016,3.54167658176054));
#629=CARTESIAN_POINT('',(-11.1493056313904,4.61825453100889,3.68748521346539));
#630=CARTESIAN_POINT('',(-11.8021776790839,2.50856434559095,3.8333513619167));
#631=CARTESIAN_POINT('',(-12.0633531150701,0.315962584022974,3.97914646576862));
#632=CARTESIAN_POINT('',(-11.9177644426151,-1.88765780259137,4.12502086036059));
#633=CARTESIAN_POINT('',(-11.3747674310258,-4.02794086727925,4.27081308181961));
#634=CARTESIAN_POINT('',(-10.4502596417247,-6.03352237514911,4.41668500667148));
#635=CARTESIAN_POINT('',(-9.17529768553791,-7.83637417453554,4.56248507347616));
#636=CARTESIAN_POINT('',(-7.59434030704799,-9.37827116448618,4.70834416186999));
#637=CARTESIAN_POINT('',(-5.75731397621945,-10.6036082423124,4.85416105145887));
#638=CARTESIAN_POINT('',(-3.72922558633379,-11.4773479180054,5.00000024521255));
#639=CARTESIAN_POINT('',(-1.57485201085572,-11.9623402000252,5.14583849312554));
#640=CARTESIAN_POINT('',(0.631550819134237,-12.0515300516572,5.29165624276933));
#641=CARTESIAN_POINT('',(2.81672677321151,-11.7322774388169,5.43751456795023));
#642=CARTESIAN_POINT('',(4.90833399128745,-11.0244622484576,5.58331520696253));
#643=CARTESIAN_POINT('',(6.83434805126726,-9.94391600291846,5.72918674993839));
#644=CARTESIAN_POINT('',(8.53274353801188,-8.53284811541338,5.87497907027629));
#645=CARTESIAN_POINT('',(9.94446517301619,-6.83456494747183,6.02085362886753));
#646=CARTESIAN_POINT('',(11.02333168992,-4.90797393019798,6.16664846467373));
#647=CARTESIAN_POINT('',(11.7338559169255,-2.81700710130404,6.31251511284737));
#648=CARTESIAN_POINT('',(12.0494652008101,-0.631524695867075,6.45832269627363));
#649=CARTESIAN_POINT('',(11.9645671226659,1.57517466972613,6.60417242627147));
#650=CARTESIAN_POINT('',(11.4751000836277,3.72848434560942,6.74999977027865));
#651=CARTESIAN_POINT('',(10.6056574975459,5.75837192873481,6.89582804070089));
#652=CARTESIAN_POINT('',(9.37668509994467,7.59314053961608,7.04167687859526));
#653=CARTESIAN_POINT('',(7.83754685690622,9.17650104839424,7.18748520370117));
#654=CARTESIAN_POINT('',(6.03286015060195,10.4493495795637,7.33335126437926));
#655=CARTESIAN_POINT('',(4.02827918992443,11.3752927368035,7.47914645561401));
#656=CARTESIAN_POINT('',(1.88752245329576,11.9177855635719,7.62502088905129));
#657=CARTESIAN_POINT('',(-0.31580290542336,12.0627488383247,7.77081308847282));
#658=CARTESIAN_POINT('',(-2.50891296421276,11.8032485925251,7.91668499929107));
#659=CARTESIAN_POINT('',(-4.61751183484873,11.1477994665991,8.06248507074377));
#660=CARTESIAN_POINT('',(-6.5724856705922,10.120691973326,8.20834416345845));
#661=CARTESIAN_POINT('',(-8.30552284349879,8.75222611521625,8.35416105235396));
#662=CARTESIAN_POINT('',(-9.76321245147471,7.09339985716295,8.50000024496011));
#663=CARTESIAN_POINT('',(-10.8902055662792,5.19433968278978,8.64583849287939));
#664=CARTESIAN_POINT('',(-11.6568461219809,3.12348707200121,8.79165624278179));
#665=CARTESIAN_POINT('',(-12.0284753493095,0.946606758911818,8.93751456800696));
#666=CARTESIAN_POINT('',(-12.0016452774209,-1.26135683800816,9.08331520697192));
#667=CARTESIAN_POINT('',(-11.5691558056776,-3.42701221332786,9.22918674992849));
#668=CARTESIAN_POINT('',(-10.7519835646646,-5.47832626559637,9.37497907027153));
#669=CARTESIAN_POINT('',(-9.57306626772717,-7.34575168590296,9.52085362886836));
#670=CARTESIAN_POINT('',(-8.0741574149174,-8.96716408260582,9.66664846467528));
#671=CARTESIAN_POINT('',(-6.30509384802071,-10.2890570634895,9.8125151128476));
#672=CARTESIAN_POINT('',(-4.32410519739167,-11.2645705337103,9.95832269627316));
#673=CARTESIAN_POINT('',(-2.19917443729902,-11.8657352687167,10.1041724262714));
#674=CARTESIAN_POINT('',(-1.60519495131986E-06,-12.065633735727,10.2499997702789));
#675=CARTESIAN_POINT('',(2.19920874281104,-11.8660144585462,10.3958280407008));
#676=CARTESIAN_POINT('',(4.32395074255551,-11.2641669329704,10.5416768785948));
#677=CARTESIAN_POINT('',(6.30543594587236,-10.2896447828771,10.6874852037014));
#678=CARTESIAN_POINT('',(8.07366569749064,-8.96661755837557,10.8333512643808));
#679=CARTESIAN_POINT('',(9.57373955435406,-7.34627994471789,10.9791464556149));
#680=CARTESIAN_POINT('',(10.7512111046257,-5.47793880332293,11.1250208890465));
#681=CARTESIAN_POINT('',(11.5699443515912,-3.427247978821,11.2708130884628));
#682=CARTESIAN_POINT('',(12.000853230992,-1.26128638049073,11.4166849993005));
#683=CARTESIAN_POINT('',(12.0290769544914,0.946655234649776,11.5624850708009));
#684=CARTESIAN_POINT('',(11.6563598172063,3.1233395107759,11.7083441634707));
#685=CARTESIAN_POINT('',(10.8904093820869,5.19443501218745,11.8541610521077));
#686=CARTESIAN_POINT('',(9.76322272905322,7.09338571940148,12.0000002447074));
#687=CARTESIAN_POINT('',(8.30536920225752,8.75206173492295,12.1458384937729));
#688=CARTESIAN_POINT('',(6.57277627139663,10.1211088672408,12.2916562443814));
#689=CARTESIAN_POINT('',(4.61727980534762,11.1472422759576,12.4375145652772));
#690=CARTESIAN_POINT('',(2.50909074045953,11.8040237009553,12.5833151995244));
#691=CARTESIAN_POINT('',(0.315783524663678,12.0619260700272,12.7291867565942));
#692=CARTESIAN_POINT('',(-1.88765223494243,11.9186397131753,12.8749790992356));
#693=CARTESIAN_POINT('',(-4.02798501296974,11.3744889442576,13.0208536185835));
#694=CARTESIAN_POINT('',(-6.03322846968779,10.4499868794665,13.1666483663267));
#695=CARTESIAN_POINT('',(-7.8370936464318,9.1759951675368,13.3125151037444));
#696=CARTESIAN_POINT('',(-9.37701853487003,7.5934104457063,13.458322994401));
#697=CARTESIAN_POINT('',(-10.6053987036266,5.75824916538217,13.6041725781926));
#698=CARTESIAN_POINT('',(-11.4751097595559,3.72848984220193,13.7499989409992));
#699=CARTESIAN_POINT('',(-11.9648654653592,1.57523319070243,13.8958273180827));
#700=CARTESIAN_POINT('',(-12.048998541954,-0.631500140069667,14.041679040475));
#701=CARTESIAN_POINT('',(-11.7344478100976,-2.81713283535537,14.1874876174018));
#702=CARTESIAN_POINT('',(-11.0227502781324,-4.90769840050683,14.3333458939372));
#703=CARTESIAN_POINT('',(-9.94535705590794,-6.83518686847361,14.4791398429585));
#704=CARTESIAN_POINT('',(-8.53194028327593,-8.53214432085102,14.6250343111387));
#705=CARTESIAN_POINT('',(-6.83442993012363,-9.94417796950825,14.7708294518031));
#706=CARTESIAN_POINT('',(-4.90864738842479,-11.0234482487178,14.9166489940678));
#707=CARTESIAN_POINT('',(-2.81706134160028,-11.7353683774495,15.0624416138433));
#708=CARTESIAN_POINT('',(-0.631513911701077,-12.046249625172,15.2084468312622));
#709=CARTESIAN_POINT('',(1.58226116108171,-11.9782283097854,15.3543091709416));
#710=CARTESIAN_POINT('',(3.00051631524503,-11.600770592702,15.4515056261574));
#711=CARTESIAN_POINT('',(3.70812820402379,-11.4124451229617,15.4999999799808));
#712=(BOUNDED_SURFACE() B_SPLINE_SURFACE(3,3,((#19,#20,#21,#22,#23,#24,#25,#26,#27,#28,#29,#30,
#31,#32,#33,#34,#35,#36,#37,#38,#39,#40,#41,#42,#43,#44,#45,#46,#47,#48,#49,#50,#51,#52,#53,#54,
#55,#56,#57,#58,#59,#60,#61,#62,#63,#64,#65,#66,#67,#68,#69,#70,#71,#72,#73,#74,#75,#76,#77,#78,
#79,#80,#81,#82,#83,#84,#85,#86,#87,#88,#89,#90,#91,#92,#93,#94,#95,#96,#97,#98,#99,#100,#101,
#102,#103,#104,#105,#106,#107,#108,#109,#110,#111,#112,#113,#114,#115,#116,#117),(#118,#119,
#120,#121,#122,#123,#124,#125,#126,#127,#128,#129,#130,#131,#132,#133,#134,#135,#136,#137,#138,
#139,#140,#141,#142,#143,#144,#145,#146,#147,#148,#149,#150,#151,#152,#153,#154,#155,#156,#157,
#158,#159,#160,#161,#162,#163,#164,#165,#166,#167,#168,#169,#170,#171,#172,#173,#174,#175,#176,
#177,#178,#179,#180,#181,#182,#183,#184,#185,#186,#187,#188,#189,#190,#191,#192,#193,#194,#195,
#196,#197,#198,#199,#200,#201,#202,#203,#204,#205,#206,#207,#208,#209,#210,#211,#212,#213,#214,
#215,#216),(#217,#218,#219,#220,#221,#222,#223,#224,#225,#226,#227,#228,#229,#230,#231,#232,
#233,#234,#235,#236,#237,#238,#239,#240,#241,#242,#243,#244,#245,#246,#247,#248,#249,#250,#251,
#252,#253,#254,#255,#256,#257,#258,#259,#260,#261,#262,#263,#264,#265,#266,#267,#268,#269,#270,
#271,#272,#273,#274,#275,#276,#277,#278,#279,#280,#281,#282,#283,#284,#285,#286,#287,#288,#289,
#290,#291,#292,#293,#294,#295,#296,#297,#298,#299,#300,#301,#302,#303,#304,#305,#306,#307,#308,
#309,#310,#311,#312,#313,#314,#315),(#316,#317,#318,#319,#320,#321,#322,#323,#324,#325,#326,
#327,#328,#329,#330,#331,#332,#333,#334,#335,#336,#337,#338,#339,#340,#341,#342,#343,#344,#345,
#346,#347,#348,#349,#350,#351,#352,#353,#354,#355,#356,#357,#358,#359,#360,#361,#362,#363,#364,
#365,#366,#367,#368,#369,#370,#371,#372,#373,#374,#375,#376,#377,#378,#379,#380,#381,#382,#383,
#384,#385,#386,#387,#388,#389,#390,#391,#392,#393,#394,#395,#396,#397,#398,#399,#400,#401,#402,
#403,#404,#405,#406,#407,#408,#409,#410,#411,#412,#413,#414),(#415,#416,#417,#418,#419,#420,
#421,#422,#423,#424,#425,#426,#427,#428,#429,#430,#431,#432,#433,#434,#435,#436,#437,#438,#439,
#440,#441,#442,#443,#444,#445,#446,#447,#448,#449,#450,#451,#452,#453,#454,#455,#456,#457,#458,
#459,#460,#461,#462,#463,#464,#465,#466,#467,#468,#469,#470,#471,#472,#473,#474,#475,#476,#477,
#478,#479,#480,#481,#482,#483,#484,#485,#486,#487,#488,#489,#490,#491,#492,#493,#494,#495,#496,
#497,#498,#499,#500,#501,#502,#503,#504,#505,#506,#507,#508,#509,#510,#511,#512,#513),(#514,
#515,#516,#517,#518,#519,#520,#521,#522,#523,#524,#525,#526,#527,#528,#529,#530,#531,#532,#533,
#534,#535,#536,#537,#538,#539,#540,#541,#542,#543,#544,#545,#546,#547,#548,#549,#550,#551,#552,
#553,#554,#555,#556,#557,#558,#559,#560,#561,#562,#563,#564,#565,#566,#567,#568,#569,#570,#571,
#572,#573,#574,#575,#576,#577,#578,#579,#580,#581,#582,#583,#584,#585,#586,#587,#588,#589,#590,
#591,#592,#593,#594,#595,#596,#597,#598,#599,#600,#601,#602,#603,#604,#605,#606,#607,#608,#609,
#610,#611,#612),(#613,#614,#615,#616,#617,#618,#619,#620,#621,#622,#623,#624,#625,#626,#627,
#628,#629,#630,#631,#632,#633,#634,#635,#636,#637,#638,#639,#640,#641,#642,#643,#644,#645,#646,
#647,#648,#649,#650,#651,#652,#653,#654,#655,#656,#657,#658,#659,#660,#661,#662,#663,#664,#665,
#666,#667,#668,#669,#670,#671,#672,#673,#674,#675,#676,#677,#678,#679,#680,#681,#682,#683,#684,
#685,#686,#687,#688,#689,#690,#691,#692,#693,#694,#695,#696,#697,#698,#699,#700,#701,#702,#703,
#704,#705,#706,#707,#708,#709,#710,#711)),.UNSPECIFIED.,.T.,.F.,
.F.) B_SPLINE_SURFACE_WITH_KNOTS((4,3,4),(4,1,1,1,1,1,1,1,1,1,1,1,1,1,1,1,1,1,1,1,1,1,1,1,1,1,1,
1,1,1,1,1,1,1,1,1,1,1,1,1,1,1,1,1,1,1,1,1,1,1,1,1,1,1,1,1,1,1,1,1,1,1,1,1,1,1,1,1,1,1,1,1,1,1,1,
1,1,1,1,1,1,1,1,1,1,1,1,1,1,1,1,1,1,1,1,1,4),(0.,0.5,1.),(0.,0.0103923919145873,
0.0208292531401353,0.031254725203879,0.0416684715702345,0.0520816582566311,0.0624996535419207,
0.0729158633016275,0.0833333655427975,0.0937492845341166,0.104166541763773,0.114582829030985,
0.12499965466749,0.135416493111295,0.145832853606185,0.1562500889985,0.166666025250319,
0.177083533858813,0.18749927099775,0.197916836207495,0.208332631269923,0.218750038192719,
0.229166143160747,0.239583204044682,0.249999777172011,0.260416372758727,0.270833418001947,
0.281249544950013,0.291666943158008,0.30208275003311,0.31250031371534,0.322916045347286,
0.333333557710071,0.343749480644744,0.35416673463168,0.364583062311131,0.374999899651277,
0.385416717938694,0.395833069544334,0.406250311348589,0.416666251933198,0.427083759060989,
0.437499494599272,0.447917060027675,0.45833285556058,0.468750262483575,0.479166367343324,
0.489583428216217,0.500000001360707,0.510416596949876,0.520833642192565,0.531249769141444,
0.541667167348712,0.552082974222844,0.56250053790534,0.572916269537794,0.583333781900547,
0.593749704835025,0.604166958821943,0.614583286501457,0.62500012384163,0.635416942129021,
0.645833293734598,0.656250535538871,0.666666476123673,0.677083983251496,0.687499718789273,
0.697917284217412,0.708333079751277,0.718750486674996,0.729166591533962,0.739583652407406,
0.75000022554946,0.760416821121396,0.770833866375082,0.781249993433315,0.791667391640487,
0.802083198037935,0.812500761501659,0.822916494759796,0.833334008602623,0.84374992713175,
0.854167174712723,0.864583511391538,0.875000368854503,0.885417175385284,0.895833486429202,
0.906250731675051,0.9166666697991,0.927084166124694,0.937500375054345,0.947918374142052,
0.958331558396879,0.968745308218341,0.979170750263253,0.989607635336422,1.),
.UNSPECIFIED.) GEOMETRIC_REPRESENTATION_ITEM() RATIONAL_B_SPLINE_SURFACE(((1.,1.,1.,1.,1.,1.,1.,
1.,1.,1.,1.,1.,1.,1.,1.,1.,1.,1.,1.,1.,1.,1.,1.,1.,1.,1.,1.,1.,1.,1.,1.,1.,1.,1.,1.,1.,1.,1.,1.,
1.,1.,1.,1.,1.,1.,1.,1.,1.,1.,1.,1.,1.,1.,1.,1.,1.,1.,1.,1.,1.,1.,1.,1.,1.,1.,1.,1.,1.,1.,1.,1.,
1.,1.,1.,1.,1.,1.,1.,1.,1.,1.,1.,1.,1.,1.,1.,1.,1.,1.,1.,1.,1.,1.,1.,1.,1.,1.,1.,1.),
(0.333333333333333,0.333333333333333,0.333333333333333,0.333333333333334,0.333333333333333,
0.333333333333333,0.333333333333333,0.333333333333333,0.333333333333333,0.333333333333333,
0.333333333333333,0.333333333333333,0.333333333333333,0.333333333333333,0.333333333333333,
0.333333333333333,0.333333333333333,0.333333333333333,0.333333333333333,0.333333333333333,
0.333333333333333,0.333333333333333,0.333333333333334,0.333333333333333,0.333333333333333,
0.333333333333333,0.333333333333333,0.333333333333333,0.333333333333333,0.333333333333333,
0.333333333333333,0.333333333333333,0.333333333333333,0.333333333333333,0.333333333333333,
0.333333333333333,0.333333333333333,0.333333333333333,0.333333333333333,0.333333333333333,
0.333333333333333,0.333333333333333,0.333333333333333,0.333333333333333,0.333333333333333,
0.333333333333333,0.333333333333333,0.333333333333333,0.333333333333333,0.333333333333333,
0.333333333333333,0.333333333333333,0.333333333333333,0.333333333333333,0.333333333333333,
0.333333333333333,0.333333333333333,0.333333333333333,0.333333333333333,0.333333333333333,
0.333333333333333,0.333333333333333,0.333333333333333,0.333333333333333,0.333333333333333,
0.333333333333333,0.333333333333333,0.333333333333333,0.333333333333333,0.333333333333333,
0.333333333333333,0.333333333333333,0.333333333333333,0.333333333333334,0.333333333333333,
0.333333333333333,0.333333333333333,0.333333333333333,0.333333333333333,0.333333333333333,
0.333333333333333,0.333333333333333,0.333333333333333,0.333333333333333,0.333333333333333,
0.333333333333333,0.333333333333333,0.333333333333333,0.333333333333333,0.333333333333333,
0.333333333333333,0.333333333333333,0.333333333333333,0.333333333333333,0.333333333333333,
0.333333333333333,0.333333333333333,0.333333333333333,0.333333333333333),(0.333333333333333,
0.333333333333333,0.333333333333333,0.333333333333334,0.333333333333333,0.333333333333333,
0.333333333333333,0.333333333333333,0.333333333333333,0.333333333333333,0.333333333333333,
0.333333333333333,0.333333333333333,0.333333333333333,0.333333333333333,0.333333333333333,
0.333333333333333,0.333333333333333,0.333333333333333,0.333333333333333,0.333333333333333,
0.333333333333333,0.333333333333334,0.333333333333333,0.333333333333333,0.333333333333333,
0.333333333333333,0.333333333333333,0.333333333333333,0.333333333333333,0.333333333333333,
0.333333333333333,0.333333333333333,0.333333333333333,0.333333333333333,0.333333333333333,
0.333333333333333,0.333333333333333,0.333333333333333,0.333333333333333,0.333333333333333,
0.333333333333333,0.333333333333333,0.333333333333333,0.333333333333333,0.333333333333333,
0.333333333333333,0.333333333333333,0.333333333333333,0.333333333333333,0.333333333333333,
0.333333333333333,0.333333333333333,0.333333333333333,0.333333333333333,0.333333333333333,
0.333333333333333,0.333333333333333,0.333333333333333,0.333333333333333,0.333333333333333,
0.333333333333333,0.333333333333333,0.333333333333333,0.333333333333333,0.333333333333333,
0.333333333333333,0.333333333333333,0.333333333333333,0.333333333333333,0.333333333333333,
0.333333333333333,0.333333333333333,0.333333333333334,0.333333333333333,0.333333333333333,
0.333333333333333,0.333333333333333,0.333333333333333,0.333333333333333,0.333333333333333,
0.333333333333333,0.333333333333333,0.333333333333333,0.333333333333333,0.333333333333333,
0.333333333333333,0.333333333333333,0.333333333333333,0.333333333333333,0.333333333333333,
0.333333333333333,0.333333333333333,0.333333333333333,0.333333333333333,0.333333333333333,
0.333333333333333,0.333333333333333,0.333333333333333),(1.,1.,1.,1.,1.,1.,1.,1.,1.,1.,1.,1.,1.,
1.,1.,1.,1.,1.,1.,1.,1.,1.,1.,1.,1.,1.,1.,1.,1.,1.,1.,1.,1.,1.,1.,1.,1.,1.,1.,1.,1.,1.,1.,1.,1.,
1.,1.,1.,1.,1.,1.,1.,1.,1.,1.,1.,1.,1.,1.,1.,1.,1.,1.,1.,1.,1.,1.,1.,1.,1.,1.,1.,1.,1.,1.,1.,1.,
1.,1.,1.,1.,1.,1.,1.,1.,1.,1.,1.,1.,1.,1.,1.,1.,1.,1.,1.,1.,1.,1.),(0.333333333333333,
0.333333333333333,0.333333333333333,0.333333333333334,0.333333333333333,0.333333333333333,
0.333333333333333,0.333333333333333,0.333333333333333,0.333333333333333,0.333333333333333,
0.333333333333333,0.333333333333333,0.333333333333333,0.333333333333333,0.333333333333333,
0.333333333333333,0.333333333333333,0.333333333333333,0.333333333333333,0.333333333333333,
0.333333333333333,0.333333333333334,0.333333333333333,0.333333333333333,0.333333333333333,
0.333333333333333,0.333333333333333,0.333333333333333,0.333333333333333,0.333333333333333,
0.333333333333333,0.333333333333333,0.333333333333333,0.333333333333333,0.333333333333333,
0.333333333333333,0.333333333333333,0.333333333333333,0.333333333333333,0.333333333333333,
0.333333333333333,0.333333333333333,0.333333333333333,0.333333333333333,0.333333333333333,
0.333333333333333,0.333333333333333,0.333333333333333,0.333333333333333,0.333333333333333,
0.333333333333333,0.333333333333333,0.333333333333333,0.333333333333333,0.333333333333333,
0.333333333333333,0.333333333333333,0.333333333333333,0.333333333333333,0.333333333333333,
0.333333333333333,0.333333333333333,0.333333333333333,0.333333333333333,0.333333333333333,
0.333333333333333,0.333333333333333,0.333333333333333,0.333333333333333,0.333333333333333,
0.333333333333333,0.333333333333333,0.333333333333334,0.333333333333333,0.333333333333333,
0.333333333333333,0.333333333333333,0.333333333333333,0.333333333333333,0.333333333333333,
0.333333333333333,0.333333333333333,0.333333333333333,0.333333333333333,0.333333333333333,
0.333333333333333,0.333333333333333,0.333333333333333,0.333333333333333,0.333333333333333,
0.333333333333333,0.333333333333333,0.333333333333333,0.333333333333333,0.333333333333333,
0.333333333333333,0.333333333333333,0.333333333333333),(0.333333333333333,0.333333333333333,
0.333333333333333,0.333333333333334,0.333333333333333,0.333333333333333,0.333333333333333,
0.333333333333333,0.333333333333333,0.333333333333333,0.333333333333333,0.333333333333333,
0.333333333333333,0.333333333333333,0.333333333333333,0.333333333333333,0.333333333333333,
0.333333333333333,0.333333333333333,0.333333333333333,0.333333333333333,0.333333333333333,
0.333333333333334,0.333333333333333,0.333333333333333,0.333333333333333,0.333333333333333,
0.333333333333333,0.333333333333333,0.333333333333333,0.333333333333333,0.333333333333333,
0.333333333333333,0.333333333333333,0.333333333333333,0.333333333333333,0.333333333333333,
0.333333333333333,0.333333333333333,0.333333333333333,0.333333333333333,0.333333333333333,
0.333333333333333,0.333333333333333,0.333333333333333,0.333333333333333,0.333333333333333,
0.333333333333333,0.333333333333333,0.333333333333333,0.333333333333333,0.333333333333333,
0.333333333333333,0.333333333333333,0.333333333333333,0.333333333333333,0.333333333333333,
0.333333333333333,0.333333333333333,0.333333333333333,0.333333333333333,0.333333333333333,
0.333333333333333,0.333333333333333,0.333333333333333,0.333333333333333,0.333333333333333,
0.333333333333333,0.333333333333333,0.333333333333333,0.333333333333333,0.333333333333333,
0.333333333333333,0.333333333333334,0.333333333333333,0.333333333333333,0.333333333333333,
0.333333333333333,0.333333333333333,0.333333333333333,0.333333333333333,0.333333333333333,
0.333333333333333,0.333333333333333,0.333333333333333,0.333333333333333,0.333333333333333,
0.333333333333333,0.333333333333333,0.333333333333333,0.333333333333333,0.333333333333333,
0.333333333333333,0.333333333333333,0.333333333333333,0.333333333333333,0.333333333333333,
0.333333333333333,0.333333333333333),(1.,1.,1.,1.,1.,1.,1.,1.,1.,1.,1.,1.,1.,1.,1.,1.,1.,1.,1.,
1.,1.,1.,1.,1.,1.,1.,1.,1.,1.,1.,1.,1.,1.,1.,1.,1.,1.,1.,1.,1.,1.,1.,1.,1.,1.,1.,1.,1.,1.,1.,1.,
1.,1.,1.,1.,1.,1.,1.,1.,1.,1.,1.,1.,1.,1.,1.,1.,1.,1.,1.,1.,1.,1.,1.,1.,1.,1.,1.,1.,1.,1.,1.,1.,
1.,1.,1.,1.,1.,1.,1.,1.,1.,1.,1.,1.,1.,1.,1.,1.))) REPRESENTATION_ITEM('') SURFACE());
#713=CARTESIAN_POINT('',(3.7082039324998,-11.4126781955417,14.));
#714=DIRECTION('',(-0.951059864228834,-0.309006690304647,-8.85042799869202E-10));
#715=DIRECTION('',(0.309006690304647,-0.951059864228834,0.));
#716=AXIS2_PLACEMENT_3D('',#713,#714,#715);
#717=CIRCLE('',#716,1.5);
#718=CARTESIAN_POINT('',(4.17171396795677,-12.839267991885,14.));
#719=VERTEX_POINT('',#718);
#720=EDGE_CURVE('E41',#719,#719,#717,.T.);
#721=CARTESIAN_POINT('',(12.,0.,0.));
#722=DIRECTION('',(0.,1.,0.));
#723=DIRECTION('',(0.,0.,1.));
#724=AXIS2_PLACEMENT_3D('',#721,#722,#723);
#725=CIRCLE('',#724,1.5);
#726=CARTESIAN_POINT('',(10.5017772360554,0.,-0.0729969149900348));
#727=VERTEX_POINT('',#726);
#728=CARTESIAN_POINT('',(13.4982227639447,0.,-0.0729969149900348));
#729=VERTEX_POINT('',#728);
#730=EDGE_CURVE('E67',#727,#729,#725,.T.);
#731=CARTESIAN_POINT('',(13.4982227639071,7.37267171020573E-10,-0.0729969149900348));
#732=CARTESIAN_POINT('',(13.4887986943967,0.165199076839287,-0.0729969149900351));
#733=CARTESIAN_POINT('',(13.4792841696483,0.33040799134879,-0.0729969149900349));
#734=CARTESIAN_POINT('',(13.4585220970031,0.661103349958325,-0.0729969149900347));
#735=CARTESIAN_POINT('',(13.4472705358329,0.826589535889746,-0.0729969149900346));
#736=CARTESIAN_POINT('',(13.4215028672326,1.1574398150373,-0.0729969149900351));
#737=CARTESIAN_POINT('',(13.4069844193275,1.32280373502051,-0.0729969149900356));
#738=CARTESIAN_POINT('',(13.3731153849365,1.65323439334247,-0.0729969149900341));
#739=CARTESIAN_POINT('',(13.3537594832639,1.81830060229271,-0.072996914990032));
#740=CARTESIAN_POINT('',(13.3086637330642,2.1474354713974,-0.0729969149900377));
#741=CARTESIAN_POINT('',(13.282929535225,2.31150488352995,-0.0729969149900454));
#742=CARTESIAN_POINT('',(13.2236409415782,2.63816449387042,-0.0729969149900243));
#743=CARTESIAN_POINT('',(13.1900896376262,2.80075525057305,-0.0729969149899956));
#744=CARTESIAN_POINT('',(13.1128237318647,3.13677668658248,-0.072996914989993));
#745=CARTESIAN_POINT('',(13.0685233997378,3.31007207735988,-0.0729969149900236));
#746=CARTESIAN_POINT('',(12.9720444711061,3.65447537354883,-0.072996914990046));
#747=CARTESIAN_POINT('',(12.9198647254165,3.82558295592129,-0.0729969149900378));
#748=CARTESIAN_POINT('',(12.8081245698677,4.16561603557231,-0.0729969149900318));
#749=CARTESIAN_POINT('',(12.7485544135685,4.33453831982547,-0.072996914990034));
#750=CARTESIAN_POINT('',(12.6226676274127,4.66984014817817,-0.0729969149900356));
#751=CARTESIAN_POINT('',(12.5563511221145,4.83621973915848,-0.0729969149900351));
#752=CARTESIAN_POINT('',(12.4172924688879,5.16630229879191,-0.0729969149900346));
#753=CARTESIAN_POINT('',(12.3445493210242,5.33000484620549,-0.0729969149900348));
#754=CARTESIAN_POINT('',(12.1926023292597,5.65438241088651,-0.0729969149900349));
#755=CARTESIAN_POINT('',(12.1133986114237,5.81505748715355,-0.0729969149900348));
#756=CARTESIAN_POINT('',(11.9486142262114,6.13295459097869,-0.0729969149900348));
#757=CARTESIAN_POINT('',(11.8630383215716,6.29017908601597,-0.0729969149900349));
#758=CARTESIAN_POINT('',(11.6854748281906,6.60096983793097,-0.0729969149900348));
#759=CARTESIAN_POINT('',(11.5934871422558,6.75453603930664,-0.0729969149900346));
#760=CARTESIAN_POINT('',(11.402385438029,7.05881449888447,-0.0729969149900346));
#761=CARTESIAN_POINT('',(11.3032223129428,7.20949596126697,-0.0729969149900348));
#762=CARTESIAN_POINT('',(11.0985876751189,7.50648332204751,-0.0729969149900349));
#763=CARTESIAN_POINT('',(10.993116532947,7.65278947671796,-0.0729969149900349));
#764=CARTESIAN_POINT('',(10.6674739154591,8.08488660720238,-0.0729969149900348));
#765=CARTESIAN_POINT('',(10.4380928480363,8.36382506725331,-0.0729969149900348));
#766=CARTESIAN_POINT('',(9.95664265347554,8.90111758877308,-0.0729969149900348));
#767=CARTESIAN_POINT('',(9.70458223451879,9.1594794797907,-0.0729969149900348));
#768=CARTESIAN_POINT('',(9.17951090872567,9.65398877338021,-0.0729969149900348));
#769=CARTESIAN_POINT('',(8.9064995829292,9.8901357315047,-0.0729969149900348));
#770=CARTESIAN_POINT('',(8.34294128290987,10.3371671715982,-0.072996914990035));
#771=CARTESIAN_POINT('',(8.0524978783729,10.5481821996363,-0.0729969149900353));
#772=CARTESIAN_POINT('',(7.45460671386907,10.9446060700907,-0.0729969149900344));
#773=CARTESIAN_POINT('',(7.1471586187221,11.1300144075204,-0.0729969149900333));
#774=CARTESIAN_POINT('',(6.51720413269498,11.4736887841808,-0.0729969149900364));
#775=CARTESIAN_POINT('',(6.19468844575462,11.6319377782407,-0.0729969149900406));
#776=CARTESIAN_POINT('',(5.53699735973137,11.9195949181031,-0.0729969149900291));
#777=CARTESIAN_POINT('',(5.20182278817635,12.0490049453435,-0.0729969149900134));
#778=CARTESIAN_POINT('',(4.69539192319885,12.2191547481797,-0.0729969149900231));
#779=CARTESIAN_POINT('',(4.52792723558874,12.2714053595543,-0.0729969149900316));
#780=CARTESIAN_POINT('',(4.19091189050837,12.3684968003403,-0.072996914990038));
#781=CARTESIAN_POINT('',(4.02136180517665,12.4133396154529,-0.072996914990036));
#782=CARTESIAN_POINT('',(3.50985893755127,12.5364703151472,-0.0729969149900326));
#783=CARTESIAN_POINT('',(3.16507723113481,12.60335246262,-0.0729969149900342));
#784=CARTESIAN_POINT('',(2.47148733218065,12.70531109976,-0.0729969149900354));
#785=CARTESIAN_POINT('',(2.12268693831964,12.7404412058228,-0.072996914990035));
#786=CARTESIAN_POINT('',(1.42342202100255,12.7776717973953,-0.0729969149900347));
#787=CARTESIAN_POINT('',(1.07295879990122,12.7797948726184,-0.0729969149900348));
#788=CARTESIAN_POINT('',(0.564711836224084,12.7573387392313,-0.0729969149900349));
#789=CARTESIAN_POINT('',(0.406223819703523,12.7467086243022,-0.0729969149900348));
#790=CARTESIAN_POINT('',(0.089946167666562,12.7178841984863,-0.0729969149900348));
#791=CARTESIAN_POINT('',(-0.0678435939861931,12.6996913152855,-0.0729969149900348));
#792=CARTESIAN_POINT('',(-0.382073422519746,12.6553298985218,-0.0729969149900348));
#793=CARTESIAN_POINT('',(-0.538515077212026,12.6291726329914,-0.0729969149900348));
#794=CARTESIAN_POINT('',(-0.849691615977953,12.5682116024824,-0.0729969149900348));
#795=CARTESIAN_POINT('',(-1.00442699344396,12.53341040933,-0.0729969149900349));
#796=CARTESIAN_POINT('',(-1.23447355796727,12.473925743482,-0.0729969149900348));
#797=CARTESIAN_POINT('',(-1.31074187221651,12.4529070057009,-0.0729969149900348));
#798=CARTESIAN_POINT('',(-1.46251166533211,12.4082091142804,-0.0729969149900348));
#799=CARTESIAN_POINT('',(-1.53801305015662,12.3845296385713,-0.0729969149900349));
#800=CARTESIAN_POINT('',(-1.68805054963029,12.3341772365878,-0.0729969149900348));
#801=CARTESIAN_POINT('',(-1.76258623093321,12.3075030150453,-0.0729969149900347));
#802=CARTESIAN_POINT('',(-1.91030044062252,12.2506656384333,-0.0729969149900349));
#803=CARTESIAN_POINT('',(-1.98347955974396,12.2205040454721,-0.0729969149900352));
#804=CARTESIAN_POINT('',(-2.09180754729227,12.1718963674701,-0.0729969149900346));
#805=CARTESIAN_POINT('',(-2.12770561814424,12.1551177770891,-0.0729969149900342));
#806=CARTESIAN_POINT('',(-2.19887103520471,12.1202216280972,-0.0729969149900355));
#807=CARTESIAN_POINT('',(-2.23413808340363,12.1021034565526,-0.0729969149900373));
#808=CARTESIAN_POINT('',(-2.3037696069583,12.0642312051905,-0.0729969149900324));
#809=CARTESIAN_POINT('',(-2.3381344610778,12.044477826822,-0.0729969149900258));
#810=CARTESIAN_POINT('',(-2.40552152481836,12.0028297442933,-0.0729969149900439));
#811=CARTESIAN_POINT('',(-2.43854508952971,11.9809372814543,-0.0729969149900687));
#812=CARTESIAN_POINT('',(-2.49229897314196,11.941366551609,-0.0729969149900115));
#813=CARTESIAN_POINT('',(-2.51363207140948,11.9245250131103,-0.0729969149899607));
#814=CARTESIAN_POINT('',(-2.54420490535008,11.897698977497,-0.0729969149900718));
#815=CARTESIAN_POINT('',(-2.55413978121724,11.8885160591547,-0.0729969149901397));
#816=CARTESIAN_POINT('',(-2.57335579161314,11.869495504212,-0.07299691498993));
#817=CARTESIAN_POINT('',(-2.58263691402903,11.8596578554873,-0.0729969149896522));
#818=CARTESIAN_POINT('',(-2.60381829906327,11.8350382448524,-0.0729969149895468));
#819=CARTESIAN_POINT('',(-2.61528470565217,11.8198504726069,-0.072996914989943));
#820=CARTESIAN_POINT('',(-2.62983707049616,11.7953339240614,-0.0729969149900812));
#821=CARTESIAN_POINT('',(-2.63426524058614,11.7868156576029,-0.0729969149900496));
#822=CARTESIAN_POINT('',(-2.64171993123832,11.7691812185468,-0.0729969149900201));
#823=CARTESIAN_POINT('',(-2.64475111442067,11.7600671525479,-0.0729969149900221));
#824=CARTESIAN_POINT('',(-2.64803587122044,11.7448358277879,-0.0729969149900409));
#825=CARTESIAN_POINT('',(-2.64890158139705,11.738853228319,-0.0729969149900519));
#826=CARTESIAN_POINT('',(-2.64965172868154,11.7268308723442,-0.0729969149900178));
#827=CARTESIAN_POINT('',(-2.64953820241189,11.7207912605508,-0.0729969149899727));
#828=CARTESIAN_POINT('',(-2.64822728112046,11.708789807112,-0.0729969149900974));
#829=CARTESIAN_POINT('',(-2.6470233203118,11.7028286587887,-0.0729969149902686));
#830=CARTESIAN_POINT('',(-2.64355358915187,11.691222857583,-0.0729969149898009));
#831=CARTESIAN_POINT('',(-2.6412870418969,11.6855784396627,-0.0729969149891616));
#832=CARTESIAN_POINT('',(-2.63537187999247,11.6737976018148,-0.0729969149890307));
#833=CARTESIAN_POINT('',(-2.63155039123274,11.6677490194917,-0.0729969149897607));
#834=CARTESIAN_POINT('',(-2.6229797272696,11.6563361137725,-0.07299691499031));
#835=CARTESIAN_POINT('',(-2.6182271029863,11.6509744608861,-0.0729969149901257));
#836=CARTESIAN_POINT('',(-2.60460623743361,11.6374304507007,-0.0729969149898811));
#837=CARTESIAN_POINT('',(-2.59515488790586,11.6298431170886,-0.072996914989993));
#838=CARTESIAN_POINT('',(-2.57530382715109,11.6160554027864,-0.0729969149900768));
#839=CARTESIAN_POINT('',(-2.56490144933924,11.6098591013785,-0.0729969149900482));
#840=CARTESIAN_POINT('',(-2.53718134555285,11.5950678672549,-0.0729969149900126));
#841=CARTESIAN_POINT('',(-2.51945184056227,11.5872577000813,-0.0729969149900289));
#842=CARTESIAN_POINT('',(-2.48340627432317,11.5732712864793,-0.0729969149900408));
#843=CARTESIAN_POINT('',(-2.46509037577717,11.5670945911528,-0.0729969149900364));
#844=CARTESIAN_POINT('',(-2.42799865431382,11.5558108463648,-0.0729969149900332));
#845=CARTESIAN_POINT('',(-2.40922053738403,11.5507114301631,-0.0729969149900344));
#846=CARTESIAN_POINT('',(-2.37147712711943,11.5413194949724,-0.0729969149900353));
#847=CARTESIAN_POINT('',(-2.35251191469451,11.5370266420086,-0.0729969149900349));
#848=CARTESIAN_POINT('',(-2.30390706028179,11.5268196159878,-0.0729969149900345));
#849=CARTESIAN_POINT('',(-2.27417980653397,11.5213263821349,-0.0729969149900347));
#850=CARTESIAN_POINT('',(-2.21456222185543,11.511297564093,-0.072996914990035));
#851=CARTESIAN_POINT('',(-2.18467185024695,11.5067622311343,-0.0729969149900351));
#852=CARTESIAN_POINT('',(-2.09478773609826,11.4941359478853,-0.0729969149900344));
#853=CARTESIAN_POINT('',(-2.03465646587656,11.4870387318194,-0.0729969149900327));
#854=CARTESIAN_POINT('',(-1.91421879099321,11.4741904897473,-0.072996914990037));
#855=CARTESIAN_POINT('',(-1.85391229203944,11.468440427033,-0.0729969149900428));
#856=CARTESIAN_POINT('',(-1.73336331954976,11.4576581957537,-0.0729969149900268));
#857=CARTESIAN_POINT('',(-1.67312097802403,11.452624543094,-0.072996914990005));
#858=CARTESIAN_POINT('',(-1.55266703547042,11.4428628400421,-0.0729969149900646));
#859=CARTESIAN_POINT('',(-1.4924554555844,11.4381345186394,-0.072996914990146));
#860=CARTESIAN_POINT('',(-1.37204214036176,11.4287200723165,-0.0729969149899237));
#861=CARTESIAN_POINT('',(-1.31184040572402,11.4240339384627,-0.0729969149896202));
#862=CARTESIAN_POINT('',(-1.16078723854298,11.412092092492,-0.0729969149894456));
#863=CARTESIAN_POINT('',(-1.06994292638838,11.4047433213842,-0.0729969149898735));
#864=CARTESIAN_POINT('',(-0.88831983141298,11.389279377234,-0.0729969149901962));
#865=CARTESIAN_POINT('',(-0.797541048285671,11.3811642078,-0.0729969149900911));
#866=CARTESIAN_POINT('',(-0.525357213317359,11.3552347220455,-0.0729969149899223));
#867=CARTESIAN_POINT('',(-0.344096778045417,11.3358358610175,-0.0729969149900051));
#868=CARTESIAN_POINT('',(0.017764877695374,11.2914624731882,-0.0729969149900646));
#869=CARTESIAN_POINT('',(0.19836604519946,11.2664875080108,-0.0729969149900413));
#870=CARTESIAN_POINT('',(0.558595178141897,11.2102227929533,-0.0729969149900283));
#871=CARTESIAN_POINT('',(0.738223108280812,11.1789328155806,-0.0729969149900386));
#872=CARTESIAN_POINT('',(1.09616261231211,11.1095649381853,-0.0729969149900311));
#873=CARTESIAN_POINT('',(1.27447425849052,11.0714874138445,-0.0729969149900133));
#874=CARTESIAN_POINT('',(1.62942604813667,10.9882532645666,-0.0729969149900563));
#875=CARTESIAN_POINT('',(1.80606620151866,10.943096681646,-0.072996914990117));
#876=CARTESIAN_POINT('',(2.33306440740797,10.7966679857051,-0.0729969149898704));
#877=CARTESIAN_POINT('',(2.68046785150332,10.6844430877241,-0.0729969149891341));
#878=CARTESIAN_POINT('',(3.36799094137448,10.4282094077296,-0.0729969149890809));
#879=CARTESIAN_POINT('',(3.70797776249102,10.2838440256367,-0.0729969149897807));
#880=CARTESIAN_POINT('',(4.37319799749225,9.96437580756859,-0.0729969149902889));
#881=CARTESIAN_POINT('',(4.6984324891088,9.78927522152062,-0.0729969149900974));
#882=CARTESIAN_POINT('',(5.33132523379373,9.40915871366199,-0.0729969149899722));
#883=CARTESIAN_POINT('',(5.63896747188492,9.20411611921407,-0.0729969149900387));
#884=CARTESIAN_POINT('',(6.23345933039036,8.76578942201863,-0.072996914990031));
#885=CARTESIAN_POINT('',(6.52030957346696,8.53250616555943,-0.0729969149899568));
#886=CARTESIAN_POINT('',(7.04339700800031,8.06319780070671,-0.0729969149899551));
#887=CARTESIAN_POINT('',(7.28184497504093,7.82963090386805,-0.0729969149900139));
#888=CARTESIAN_POINT('',(7.73715548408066,7.34227043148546,-0.0729969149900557));
#889=CARTESIAN_POINT('',(7.95401962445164,7.08847835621,-0.0729969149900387));
#890=CARTESIAN_POINT('',(8.26154875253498,6.69421567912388,-0.0729969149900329));
#891=CARTESIAN_POINT('',(8.36107518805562,6.5605665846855,-0.0729969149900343));
#892=CARTESIAN_POINT('',(8.55403350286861,6.28897295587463,-0.0729969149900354));
#893=CARTESIAN_POINT('',(8.64746687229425,6.15102948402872,-0.072996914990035));
#894=CARTESIAN_POINT('',(8.82802379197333,5.87105572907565,-0.0729969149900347));
#895=CARTESIAN_POINT('',(8.91514677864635,5.72902508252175,-0.0729969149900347));
#896=CARTESIAN_POINT('',(9.08279684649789,5.44113099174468,-0.072996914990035));
#897=CARTESIAN_POINT('',(9.16332403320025,5.29526760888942,-0.0729969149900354));
#898=CARTESIAN_POINT('',(9.33775472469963,4.96170366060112,-0.0729969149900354));
#899=CARTESIAN_POINT('',(9.42970222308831,4.77297411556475,-0.0729969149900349));
#900=CARTESIAN_POINT('',(9.55964452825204,4.48628948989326,-0.0729969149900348));
#901=CARTESIAN_POINT('',(9.60163244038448,4.390120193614,-0.0729969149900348));
#902=CARTESIAN_POINT('',(9.68295412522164,4.19665930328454,-0.0729969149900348));
#903=CARTESIAN_POINT('',(9.722287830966,4.09936768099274,-0.0729969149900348));
#904=CARTESIAN_POINT('',(9.79832306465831,3.90373193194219,-0.0729969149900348));
#905=CARTESIAN_POINT('',(9.835023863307,3.80538752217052,-0.0729969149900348));
#906=CARTESIAN_POINT('',(9.90575826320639,3.60774435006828,-0.0729969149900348));
#907=CARTESIAN_POINT('',(9.9397918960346,3.50844559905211,-0.0729969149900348));
#908=CARTESIAN_POINT('',(10.0050270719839,3.30888953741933,-0.0729969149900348));
#909=CARTESIAN_POINT('',(10.0362278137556,3.20863196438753,-0.0729969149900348));
#910=CARTESIAN_POINT('',(10.0956199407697,3.0072263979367,-0.0729969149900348));
#911=CARTESIAN_POINT('',(10.1238112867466,2.90607839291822,-0.0729969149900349));
#912=CARTESIAN_POINT('',(10.1769854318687,2.70299691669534,-0.0729969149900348));
#913=CARTESIAN_POINT('',(10.2019698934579,2.60106388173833,-0.0729969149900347));
#914=CARTESIAN_POINT('',(10.2485577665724,2.39642961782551,-0.072996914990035));
#915=CARTESIAN_POINT('',(10.2701612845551,2.29372841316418,-0.0729969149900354));
#916=CARTESIAN_POINT('',(10.3097561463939,2.08770695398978,-0.0729969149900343));
#917=CARTESIAN_POINT('',(10.327750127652,1.98438720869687,-0.0729969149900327));
#918=CARTESIAN_POINT('',(10.3599916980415,1.77716993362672,-0.0729969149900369));
#919=CARTESIAN_POINT('',(10.374239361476,1.67327241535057,-0.0729969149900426));
#920=CARTESIAN_POINT('',(10.3975511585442,1.48230589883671,-0.0729969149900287));
#921=CARTESIAN_POINT('',(10.407082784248,1.39529253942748,-0.0729969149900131));
#922=CARTESIAN_POINT('',(10.4243616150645,1.22107990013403,-0.0729969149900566));
#923=CARTESIAN_POINT('',(10.4321086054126,1.13388059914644,-0.0729969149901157));
#924=CARTESIAN_POINT('',(10.4461955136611,0.959353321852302,-0.072996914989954));
#925=CARTESIAN_POINT('',(10.4525351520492,0.872025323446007,-0.0729969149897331));
#926=CARTESIAN_POINT('',(10.4641678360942,0.697502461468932,-0.0729969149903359));
#927=CARTESIAN_POINT('',(10.469463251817,0.610307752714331,-0.0729969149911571));
#928=CARTESIAN_POINT('',(10.4793974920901,0.435904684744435,-0.0729969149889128));
#929=CARTESIAN_POINT('',(10.4840364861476,0.34869633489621,-0.0729969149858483));
#930=CARTESIAN_POINT('',(10.4930279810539,0.174324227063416,-0.0729969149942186));
#931=CARTESIAN_POINT('',(10.4973806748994,0.0871604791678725,-0.0729969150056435));
#932=CARTESIAN_POINT('',(10.5017772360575,0.,-0.0729969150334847));
#933=B_SPLINE_CURVE_WITH_KNOTS('',3,(#731,#732,#733,#734,#735,#736,#737,#738,#739,#740,#741,
#742,#743,#744,#745,#746,#747,#748,#749,#750,#751,#752,#753,#754,#755,#756,#757,#758,#759,#760,
#761,#762,#763,#764,#765,#766,#767,#768,#769,#770,#771,#772,#773,#774,#775,#776,#777,#778,#779,
#780,#781,#782,#783,#784,#785,#786,#787,#788,#789,#790,#791,#792,#793,#794,#795,#796,#797,#798,
#799,#800,#801,#802,#803,#804,#805,#806,#807,#808,#809,#810,#811,#812,#813,#814,#815,#816,#817,
#818,#819,#820,#821,#822,#823,#824,#825,#826,#827,#828,#829,#830,#831,#832,#833,#834,#835,#836,
#837,#838,#839,#840,#841,#842,#843,#844,#845,#846,#847,#848,#849,#850,#851,#852,#853,#854,#855,
#856,#857,#858,#859,#860,#861,#862,#863,#864,#865,#866,#867,#868,#869,#870,#871,#872,#873,#874,
#875,#876,#877,#878,#879,#880,#881,#882,#883,#884,#885,#886,#887,#888,#889,#890,#891,#892,#893,
#894,#895,#896,#897,#898,#899,#900,#901,#902,#903,#904,#905,#906,#907,#908,#909,#910,#911,#912,
#913,#914,#915,#916,#917,#918,#919,#920,#921,#922,#923,#924,#925,#926,#927,#928,#929,#930,#931,
#932),.UNSPECIFIED.,.F.,.F.,(4,2,2,2,2,2,2,2,2,2,2,2,2,2,2,2,2,2,2,2,2,2,2,2,2,2,2,2,2,2,2,2,2,
2,2,2,2,2,2,2,2,2,2,2,2,2,2,2,2,2,2,2,2,2,2,2,2,2,2,2,2,2,2,2,2,2,2,2,2,2,2,2,2,2,2,2,2,2,2,2,2,
2,2,2,2,2,2,2,2,2,2,2,2,2,2,2,2,2,2,2,4),(0.,0.496427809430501,0.99402022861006,
1.49197027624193,1.99046987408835,2.48852940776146,2.98639228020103,3.52279864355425,
4.05928331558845,4.59648317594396,5.13367311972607,5.67094679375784,6.20820998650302,
6.74507556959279,7.28194929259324,7.82292763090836,8.36387422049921,9.44587753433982,
10.5274671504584,11.6090784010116,12.6848006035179,13.7605440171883,14.8369601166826,
15.9133059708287,16.4394419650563,16.9654366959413,18.0175008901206,19.0677852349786,
20.1173507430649,20.5937428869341,21.0700451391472,21.5456766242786,22.0211667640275,
22.2584636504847,22.4957892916,22.7332179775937,22.9705407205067,23.0893972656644,
23.2083085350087,23.327169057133,23.4459063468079,23.52734174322,23.5678991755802,
23.6084573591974,23.6652095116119,23.6939354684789,23.7225648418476,23.7406338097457,
23.75866520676,23.7768059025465,23.794959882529,23.8163039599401,23.8377286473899,
23.8738829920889,23.9101420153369,23.9681079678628,24.0260579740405,24.0844057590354,
24.1427293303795,24.2333940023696,24.3240824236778,24.5056893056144,24.6874256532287,
24.8687798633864,25.0499708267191,25.2311224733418,25.5045434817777,25.7779632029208,
26.3247788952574,26.8716375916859,27.418515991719,27.9653641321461,28.5122090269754,
29.6059973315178,30.7125863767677,31.8190944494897,32.926594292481,34.0340609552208,
35.0341659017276,36.0341967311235,36.5339685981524,37.0336177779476,37.5333115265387,
38.0329972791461,38.6624295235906,38.9772058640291,39.2919901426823,39.6068612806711,
39.9217286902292,40.2366848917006,40.5516452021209,40.8664415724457,41.1812280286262,
41.4957836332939,41.8103329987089,42.072914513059,42.3355276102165,42.5981928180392,
42.8602548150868,43.1222490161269,43.3840647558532),.UNSPECIFIED.);
#934=EDGE_CURVE('E52',#729,#727,#933,.T.);
#935=ORIENTED_EDGE('',*,*,#720,.T.);
#936=EDGE_LOOP('',(#935));
#937=FACE_BOUND('',#936,.T.);
#938=ORIENTED_EDGE('',*,*,#730,.T.);
#939=ORIENTED_EDGE('',*,*,#934,.T.);
#940=EDGE_LOOP('',(#938,#939));
#941=FACE_BOUND('',#940,.T.);
#942=ADVANCED_FACE('F33',(#937,#941),#712,.T.);
#943=CARTESIAN_POINT('',(0.,0.,0.));
#944=DIRECTION('',(0.,0.,1.));
#945=DIRECTION('',(1.,0.,0.));
#946=AXIS2_PLACEMENT_3D('',#943,#944,#945);
#947=TOROIDAL_SURFACE('',#946,12.,1.5);
#948=CARTESIAN_POINT('',(0.,0.,-0.0729969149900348));
#949=DIRECTION('',(0.,0.,-1.));
#950=DIRECTION('',(-1.,0.,0.));
#951=AXIS2_PLACEMENT_3D('',#948,#949,#950);
#952=CIRCLE('',#951,13.4982227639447);
#953=CARTESIAN_POINT('',(-6.74911138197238,-11.6898038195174,-0.0729969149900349));
#954=VERTEX_POINT('',#953);
#955=EDGE_CURVE('E48',#729,#954,#952,.T.);
#956=ORIENTED_EDGE('',*,*,#955,.F.);
#957=ORIENTED_EDGE('',*,*,#730,.F.);
#958=CARTESIAN_POINT('',(0.,0.,-0.0729969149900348));
#959=DIRECTION('',(0.,0.,1.));
#960=DIRECTION('',(1.,0.,0.));
#961=AXIS2_PLACEMENT_3D('',#958,#959,#960);
#962=CIRCLE('',#961,10.5017772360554);
#963=CARTESIAN_POINT('',(-5.25088861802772,-9.09480587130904,-0.0729969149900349));
#964=VERTEX_POINT('',#963);
#965=EDGE_CURVE('E58',#964,#727,#962,.T.);
#966=ORIENTED_EDGE('',*,*,#965,.F.);
#967=CARTESIAN_POINT('',(-6.00000000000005,-10.3923048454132,0.));
#968=DIRECTION('',(-0.866025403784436,0.500000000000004,0.));
#969=DIRECTION('',(0.,0.,-1.));
#970=AXIS2_PLACEMENT_3D('',#967,#968,#969);
#971=CIRCLE('',#970,1.5);
#972=EDGE_CURVE('E65',#954,#964,#971,.T.);
#973=ORIENTED_EDGE('',*,*,#972,.F.);
#974=EDGE_LOOP('',(#956,#957,#966,#973));
#975=FACE_BOUND('',#974,.T.);
#976=ADVANCED_FACE('F64',(#975),#947,.T.);
#977=CARTESIAN_POINT('',(-6.00000000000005,-10.3923048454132,0.));
#978=DIRECTION('',(-0.866025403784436,0.500000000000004,0.));
#979=DIRECTION('',(0.,0.,-1.));
#980=AXIS2_PLACEMENT_3D('',#977,#978,#979);
#981=PLANE('',#980);
#982=ORIENTED_EDGE('',*,*,#972,.T.);
#983=DIRECTION('',(-0.500000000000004,-0.866025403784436,0.));
#984=VECTOR('',#983,1.);
#985=CARTESIAN_POINT('',(-6.00000000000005,-10.3923048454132,-0.0729969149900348));
#986=LINE('',#985,#984);
#987=EDGE_CURVE('E11',#964,#954,#986,.T.);
#988=ORIENTED_EDGE('',*,*,#987,.T.);
#989=EDGE_LOOP('',(#982,#988));
#990=FACE_BOUND('',#989,.T.);
#991=ADVANCED_FACE('F69',(#990),#981,.T.);
#992=CARTESIAN_POINT('',(3.70827966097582,-11.4129112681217,12.5000000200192));
#993=DIRECTION('',(-0.951059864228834,-0.309006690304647,-8.85042665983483E-10));
#994=DIRECTION('',(0.309006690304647,-0.951059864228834,0.));
#995=AXIS2_PLACEMENT_3D('',#992,#993,#994);
#996=PLANE('',#995);
#997=ORIENTED_EDGE('',*,*,#720,.F.);
#998=EDGE_LOOP('',(#997));
#999=FACE_BOUND('',#998,.T.);
#1000=ADVANCED_FACE('F35',(#999),#996,.F.);
#1001=CARTESIAN_POINT('',(-66.8677503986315,13.7584544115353,-0.0729969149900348));
#1002=DIRECTION('',(0.,0.,-1.));
#1003=DIRECTION('',(-1.,0.,0.));
#1004=AXIS2_PLACEMENT_3D('',#1001,#1002,#1003);
#1005=PLANE('',#1004);
#1006=ORIENTED_EDGE('',*,*,#934,.F.);
#1007=ORIENTED_EDGE('',*,*,#955,.T.);
#1008=ORIENTED_EDGE('',*,*,#987,.F.);
#1009=ORIENTED_EDGE('',*,*,#965,.T.);
#1010=EDGE_LOOP('',(#1006,#1007,#1008,#1009));
#1011=FACE_BOUND('',#1010,.T.);
#1012=ADVANCED_FACE('F57',(#1011),#1005,.T.);
#1013=CLOSED_SHELL('',(#942,#976,#991,#1000,#1012));
#1014=MANIFOLD_SOLID_BREP('B2',#1013);
#1015=ADVANCED_BREP_SHAPE_REPRESENTATION('',(#18,#1014),#14);
#1016=SHAPE_DEFINITION_REPRESENTATION(#9,#1015);
ENDSEC;
END-ISO-10303-21;
